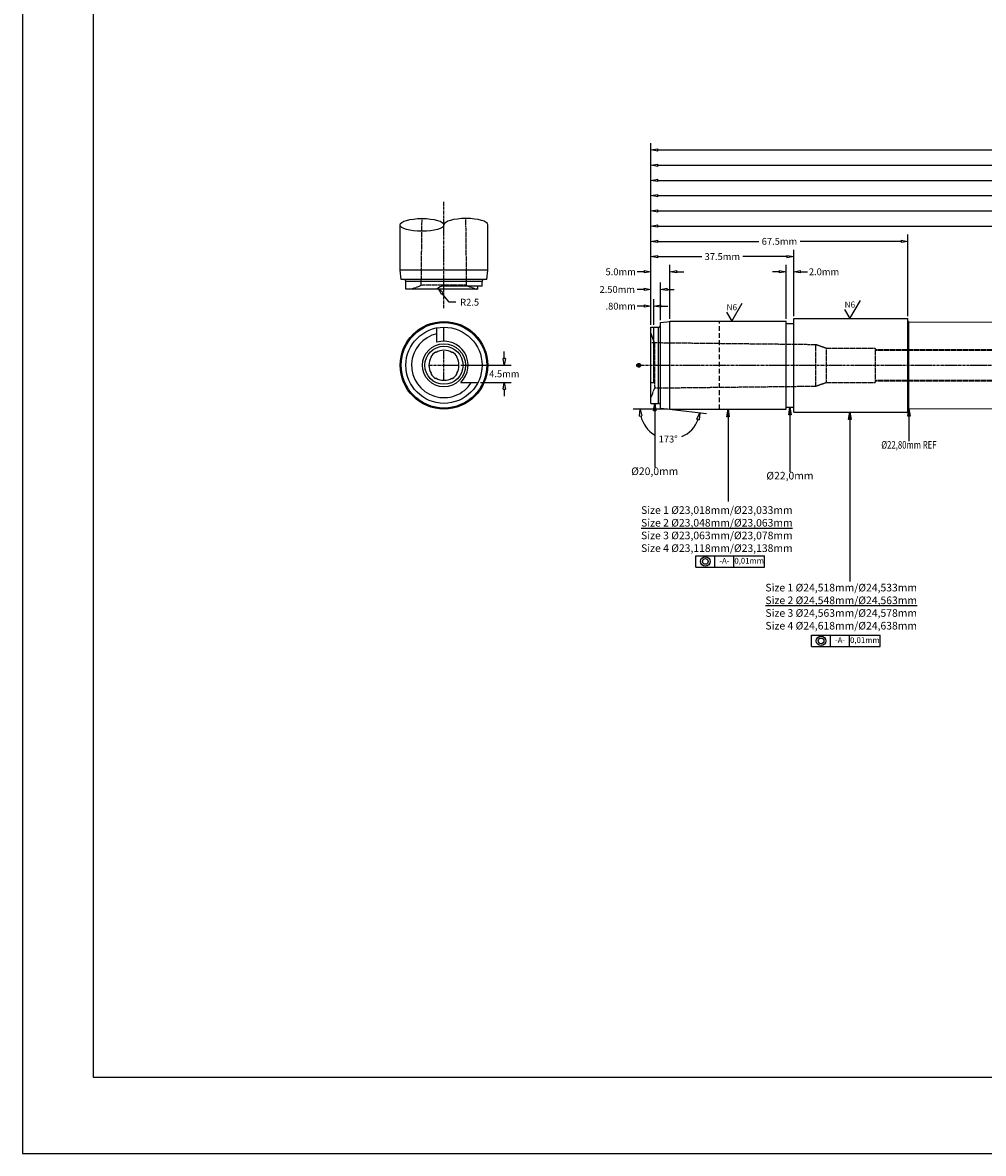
# Model space of a CAD drawing. Units: inches. Extents: x 0 to 841, y 0 to 594.
# Drawn here: x 0 to 252, y 0 to 297 of the extents above; entities that cross this region are included whole.
import ezdxf
from ezdxf.enums import TextEntityAlignment as Align

# ---------------------------------------------------------------- set-up
doc = ezdxf.new("R2010")
doc.units = ezdxf.units.IN
doc.header["$MEASUREMENT"] = 0
doc.linetypes.add('CENTER2', pattern=[1.125, 0.75, -0.125, 0.125, -0.125])
doc.linetypes.add('HIDDEN2', pattern=[0.1875, 0.125, -0.0625])
for name, color, linetype in [('CENTER', 1, 'CENTER2'), ('CENTERLINE', 1, 'CENTER2'), ('HIDDEN', 5, 'HIDDEN2'), ('TEXT', 5, 'Continuous')]:
    doc.layers.add(name, color=color, linetype=linetype)
doc.dimstyles.get("Standard").update_dxf_attribs({"dimscale": 10, "dimtxt": 0.18, "dimasz": 0.18, "dimexe": 0.18, "dimexo": 0.0625, "dimgap": 0.09, "dimtad": 0, "dimtih": 1, "dimtoh": 1, "dimdec": 4, "dimzin": 0, "dimdsep": 46, "dimtxsty": 'Standard', "dimblk": 'CLOSEDBLANK', "dimcen": 0.09, "dimadec": 4, "dimazin": 0, "dimtfac": 1, "dimtdec": 4, "dimtofl": 0, "dimtmove": 0, "dimatfit": 3, "dimldrblk": 'CLOSEDBLANK', "dimfxl": 0, "dimtolj": 1, "dimtzin": 0, "dimarcsym": 0})
doc.dimstyles.new('Standard$0', dxfattribs={"dimscale": 10, "dimtxt": 0.18, "dimasz": 0.18, "dimexe": 0.18, "dimexo": 0.0625, "dimgap": 0.09, "dimtad": 0, "dimtih": 1, "dimtoh": 1, "dimdec": 4, "dimzin": 4, "dimdsep": 46, "dimtxsty": 'Standard', "dimblk": 'CLOSEDBLANK', "dimcen": 0.09, "dimadec": 5, "dimazin": 1, "dimtfac": 1, "dimtdec": 4, "dimtofl": 0, "dimtmove": 0, "dimatfit": 3, "dimldrblk": 'CLOSEDBLANK', "dimfxl": 0, "dimtolj": 1, "dimtzin": 0, "dimarcsym": 0})

# ---------------------------------------------------------------- blocks, each defined once
blk = doc.blocks.new('_ClosedBlank')
at = {"color": 0, "linetype": 'ByBlock', "lineweight": -2}
for p, q in [((-1, 0.17), (0, 0)), ((-1, 0.17), (-1, -0.17)), ((0, 0), (-1, -0.17))]:
    blk.add_line(p, q, dxfattribs=at)
blk = doc.blocks.new('*D7')
at = {"color": 0, "lineweight": -2}
for p, q in [((165, 217.63), (165, 233.35)), ((170, 219.19), (170, 233.35)), ((163.2, 231.55), (161.4, 231.55)), ((171.8, 231.55), (173.6, 231.55))]:
    blk.add_line(p, q, dxfattribs=at)
at = {"layer": 'Defpoints', "color": 0}
for p in [(170, 231.55), (165, 217), (170, 218.57)]:
    blk.add_point(p, dxfattribs=at)
at = {"color": 0, "lineweight": -2, "xscale": 1.8, "yscale": 1.8, "zscale": 1.8}
blk.add_blockref('_ClosedBlank', (165, 231.55), dxfattribs=at)
at = {"color": 0, "lineweight": -2, "xscale": 1.8, "yscale": 1.8, "zscale": 1.8, "rotation": 180}
blk.add_blockref('_ClosedBlank', (170, 231.55), dxfattribs=at)
at = {"color": 0, "insert": (157.05, 231.55), "char_height": 1.8, "attachment_point": 5}
blk.add_mtext('\\A1;5.0mm', dxfattribs=at)
blk = doc.blocks.new('*D8')
at = {"color": 0, "lineweight": -2}
for p, q in [((165, 217.63), (165, 237.35)), ((166.8, 235.55), (178.35, 235.55)), ((200.7, 235.55), (189.15, 235.55)), ((202.5, 219.9), (202.5, 237.35))]:
    blk.add_line(p, q, dxfattribs=at)
at = {"layer": 'Defpoints', "color": 0}
for p in [(202.5, 235.55), (165, 217), (202.5, 219.28)]:
    blk.add_point(p, dxfattribs=at)
at = {"color": 0, "lineweight": -2, "xscale": 1.8, "yscale": 1.8, "zscale": 1.8, "rotation": 180}
blk.add_blockref('_ClosedBlank', (165, 235.55), dxfattribs=at)
at = {"color": 0, "lineweight": -2, "xscale": 1.8, "yscale": 1.8, "zscale": 1.8}
blk.add_blockref('_ClosedBlank', (202.5, 235.55), dxfattribs=at)
at = {"color": 0, "insert": (183.75, 235.55), "char_height": 1.8, "attachment_point": 5}
blk.add_mtext('\\A1;37.5mm', dxfattribs=at)
blk = doc.blocks.new('*D9')
at = {"color": 0, "lineweight": -2}
for p, q in [((165, 217.63), (165, 241.35)), ((232.5, 219.9), (232.5, 241.35)), ((166.8, 239.55), (193.35, 239.55)), ((230.7, 239.55), (204.15, 239.55))]:
    blk.add_line(p, q, dxfattribs=at)
at = {"layer": 'Defpoints', "color": 0}
for p in [(165, 239.55), (165, 217), (232.5, 219.28)]:
    blk.add_point(p, dxfattribs=at)
at = {"color": 0, "lineweight": -2, "xscale": 1.8, "yscale": 1.8, "zscale": 1.8, "rotation": 180}
blk.add_blockref('_ClosedBlank', (165, 239.55), dxfattribs=at)
at = {"color": 0, "lineweight": -2, "xscale": 1.8, "yscale": 1.8, "zscale": 1.8}
blk.add_blockref('_ClosedBlank', (232.5, 239.55), dxfattribs=at)
at = {"color": 0, "insert": (198.75, 239.55), "char_height": 1.8, "attachment_point": 5}
blk.add_mtext('\\A1;67.5mm', dxfattribs=at)
blk = doc.blocks.new('*D10')
at = {"color": 0, "lineweight": -2}
for p, q in [((165, 217.63), (165, 245.35)), ((166.8, 243.55), (262.5, 243.55)), ((370.2, 243.55), (274.5, 243.55)), ((372, 218.63), (372, 245.35))]:
    blk.add_line(p, q, dxfattribs=at)
at = {"layer": 'Defpoints', "color": 0}
for p in [(165, 243.55), (165, 217), (372, 218)]:
    blk.add_point(p, dxfattribs=at)
at = {"color": 0, "lineweight": -2, "xscale": 1.8, "yscale": 1.8, "zscale": 1.8, "rotation": 180}
blk.add_blockref('_ClosedBlank', (165, 243.55), dxfattribs=at)
at = {"color": 0, "lineweight": -2, "xscale": 1.8, "yscale": 1.8, "zscale": 1.8}
blk.add_blockref('_ClosedBlank', (372, 243.55), dxfattribs=at)
at = {"color": 0, "insert": (268.5, 243.55), "char_height": 1.8, "attachment_point": 5}
blk.add_mtext('\\A1;207.0mm', dxfattribs=at)
blk = doc.blocks.new('*D11')
at = {"color": 0, "lineweight": -2}
for p, q in [((165, 217.63), (165, 249.35)), ((166.8, 247.55), (274, 247.55)), ((393.2, 247.55), (286, 247.55)), ((395, 218.33), (395, 249.35))]:
    blk.add_line(p, q, dxfattribs=at)
at = {"layer": 'Defpoints', "color": 0}
for p in [(165, 247.55), (165, 217), (395, 217.7)]:
    blk.add_point(p, dxfattribs=at)
at = {"color": 0, "lineweight": -2, "xscale": 1.8, "yscale": 1.8, "zscale": 1.8, "rotation": 180}
blk.add_blockref('_ClosedBlank', (165, 247.55), dxfattribs=at)
at = {"color": 0, "lineweight": -2, "xscale": 1.8, "yscale": 1.8, "zscale": 1.8}
blk.add_blockref('_ClosedBlank', (395, 247.55), dxfattribs=at)
at = {"color": 0, "insert": (280, 247.55), "char_height": 1.8, "attachment_point": 5}
blk.add_mtext('\\A1;230.0mm', dxfattribs=at)
blk = doc.blocks.new('*D12')
at = {"color": 0, "lineweight": -2}
for p, q in [((165, 217.63), (165, 253.35)), ((447, 217.38), (447, 253.35)), ((166.8, 251.55), (299.85, 251.55)), ((445.2, 251.55), (312.15, 251.55))]:
    blk.add_line(p, q, dxfattribs=at)
at = {"layer": 'Defpoints', "color": 0}
for p in [(165, 251.55), (165, 217), (447, 216.75)]:
    blk.add_point(p, dxfattribs=at)
at = {"color": 0, "lineweight": -2, "xscale": 1.8, "yscale": 1.8, "zscale": 1.8, "rotation": 180}
blk.add_blockref('_ClosedBlank', (165, 251.55), dxfattribs=at)
at = {"color": 0, "lineweight": -2, "xscale": 1.8, "yscale": 1.8, "zscale": 1.8}
blk.add_blockref('_ClosedBlank', (447, 251.55), dxfattribs=at)
at = {"color": 0, "insert": (306, 251.55), "char_height": 1.8, "attachment_point": 5}
blk.add_mtext('\\A1;282.0mm', dxfattribs=at)
blk = doc.blocks.new('*D13')
at = {"color": 0, "lineweight": -2}
for p, q in [((165, 217.63), (165, 257.35)), ((166.8, 255.55), (320.85, 255.55)), ((487.2, 255.55), (333.15, 255.55)), ((489, 217.13), (489, 257.35))]:
    blk.add_line(p, q, dxfattribs=at)
at = {"layer": 'Defpoints', "color": 0}
for p in [(165, 255.55), (165, 217), (489, 216.5)]:
    blk.add_point(p, dxfattribs=at)
at = {"color": 0, "lineweight": -2, "xscale": 1.8, "yscale": 1.8, "zscale": 1.8, "rotation": 180}
blk.add_blockref('_ClosedBlank', (165, 255.55), dxfattribs=at)
at = {"color": 0, "lineweight": -2, "xscale": 1.8, "yscale": 1.8, "zscale": 1.8}
blk.add_blockref('_ClosedBlank', (489, 255.55), dxfattribs=at)
at = {"color": 0, "insert": (327, 255.55), "char_height": 1.8, "attachment_point": 5}
blk.add_mtext('\\A1;324.0mm', dxfattribs=at)
blk = doc.blocks.new('*D14')
at = {"color": 0, "lineweight": -2}
for p, q in [((165, 217.63), (165, 261.35)), ((166.8, 259.55), (413.6, 259.55)), ((672.7, 259.55), (425.9, 259.55)), ((674.5, 215.38), (674.5, 261.35))]:
    blk.add_line(p, q, dxfattribs=at)
at = {"layer": 'Defpoints', "color": 0}
for p in [(674.5, 259.55), (165, 217), (674.5, 214.75)]:
    blk.add_point(p, dxfattribs=at)
at = {"color": 0, "lineweight": -2, "xscale": 1.8, "yscale": 1.8, "zscale": 1.8, "rotation": 180}
blk.add_blockref('_ClosedBlank', (165, 259.55), dxfattribs=at)
at = {"color": 0, "lineweight": -2, "xscale": 1.8, "yscale": 1.8, "zscale": 1.8}
blk.add_blockref('_ClosedBlank', (674.5, 259.55), dxfattribs=at)
at = {"color": 0, "insert": (419.75, 259.55), "char_height": 1.8, "attachment_point": 5}
blk.add_mtext('\\A1;509.5mm', dxfattribs=at)
blk = doc.blocks.new('*D15')
at = {"color": 0, "lineweight": -2}
for p, q in [((165, 217.63), (165, 265.35)), ((715, 214.65), (715, 265.35)), ((166.8, 263.55), (434, 263.55)), ((713.2, 263.55), (446, 263.55))]:
    blk.add_line(p, q, dxfattribs=at)
at = {"layer": 'Defpoints', "color": 0}
for p in [(715, 263.55), (165, 217), (715, 214.03)]:
    blk.add_point(p, dxfattribs=at)
at = {"color": 0, "lineweight": -2, "xscale": 1.8, "yscale": 1.8, "zscale": 1.8, "rotation": 180}
blk.add_blockref('_ClosedBlank', (165, 263.55), dxfattribs=at)
at = {"color": 0, "lineweight": -2, "xscale": 1.8, "yscale": 1.8, "zscale": 1.8}
blk.add_blockref('_ClosedBlank', (715, 263.55), dxfattribs=at)
at = {"color": 0, "insert": (440, 263.55), "char_height": 1.8, "attachment_point": 5}
blk.add_mtext('\\A1;550.0mm', dxfattribs=at)
blk = doc.blocks.new('*D16')
at = {"color": 0, "lineweight": -2}
for p, q in [((200.5, 219.19), (200.5, 233.35)), ((202.5, 219.9), (202.5, 233.35)), ((198.7, 231.55), (196.9, 231.55)), ((204.3, 231.55), (206.1, 231.55))]:
    blk.add_line(p, q, dxfattribs=at)
at = {"layer": 'Defpoints', "color": 0}
for p in [(202.5, 231.55), (200.5, 218.57), (202.5, 219.28)]:
    blk.add_point(p, dxfattribs=at)
at = {"color": 0, "lineweight": -2, "xscale": 1.8, "yscale": 1.8, "zscale": 1.8}
blk.add_blockref('_ClosedBlank', (200.5, 231.55), dxfattribs=at)
at = {"color": 0, "lineweight": -2, "xscale": 1.8, "yscale": 1.8, "zscale": 1.8, "rotation": 180}
blk.add_blockref('_ClosedBlank', (202.5, 231.55), dxfattribs=at)
at = {"color": 0, "insert": (210.45, 231.55), "char_height": 1.8, "attachment_point": 5}
blk.add_mtext('\\A1;2.0mm', dxfattribs=at)
blk = doc.blocks.new('*D18')
at = {"color": 0, "lineweight": -2}
for p, q in [((169.38, 195.47), (160.34, 195.47)), ((170.62, 195.39), (179.59, 194.29))]:
    blk.add_line(p, q, dxfattribs=at)
for start, end in [(193.089, 238.7085), (293.3479, 339.8547)]:
    blk.add_arc((170, 195.47), 7.86, start, end, dxfattribs=at)
at = {"layer": 'Defpoints', "color": 0}
for p in [(167.5, 195.77), (170, 195.47), (170, 195.47), (200.5, 195.44), (165.79, 188.82)]:
    blk.add_point(p, dxfattribs=at)
at = {"color": 0, "lineweight": -2, "xscale": 1.8, "yscale": 1.8, "zscale": 1.8}
for p, rotation in [((162.14, 195.47), 96.51630221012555), ((177.8, 194.51), 76.42734130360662)]:
    blk.add_blockref('_ClosedBlank', p, dxfattribs=dict(at, rotation=rotation))
at = {"color": 0, "insert": (169.52, 187.62), "char_height": 1.8, "attachment_point": 5}
blk.add_mtext('\\A1;173°', dxfattribs=at)
blk = doc.blocks.new('*D19')
at = {"color": 0, "lineweight": -2}
for p, q in [((126.5, 208.8), (126.5, 210.6)), ((115.09, 207), (128.3, 207)), ((120.21, 202.5), (128.3, 202.5)), ((126.5, 200.7), (126.5, 198.9))]:
    blk.add_line(p, q, dxfattribs=at)
at = {"layer": 'Defpoints', "color": 0}
for p in [(114.46, 207), (126.5, 207), (119.58, 202.5)]:
    blk.add_point(p, dxfattribs=at)
at = {"color": 0, "lineweight": -2, "xscale": 1.8, "yscale": 1.8, "zscale": 1.8}
for p, rotation in [((126.5, 207), 270), ((126.5, 202.5), 90)]:
    blk.add_blockref('_ClosedBlank', p, dxfattribs=dict(at, rotation=rotation))
at = {"color": 0, "insert": (126.5, 204.75), "char_height": 1.8, "attachment_point": 5}
blk.add_mtext('\\A1;4.5mm', dxfattribs=at)
blk = doc.blocks.new('*D20')
at = {"color": 0, "lineweight": -2}
for p, q in [((111.99, 223.56), (110.22, 225.85)), ((113.79, 223.56), (111.99, 223.56))]:
    blk.add_line(p, q, dxfattribs=at)
at = {"layer": 'Defpoints', "color": 0}
for p in [(109.12, 227.28), (110.65, 225.3)]:
    blk.add_point(p, dxfattribs=at)
at = {"color": 0, "lineweight": -2, "xscale": 1.8, "yscale": 1.8, "zscale": 1.8, "rotation": 127.7379653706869}
blk.add_blockref('_ClosedBlank', (109.12, 227.28), dxfattribs=at)
at = {"color": 0, "insert": (117.39, 223.56), "char_height": 1.8, "attachment_point": 5}
blk.add_mtext('\\A1;R2.5', dxfattribs=at)
blk = doc.blocks.new('*D21')
at = {"color": 0, "lineweight": -2}
for p, q in [((165, 217.63), (165, 224.33)), ((165.8, 217.63), (165.8, 224.33)), ((163.2, 222.53), (161.4, 222.53)), ((167.6, 222.53), (169.4, 222.53))]:
    blk.add_line(p, q, dxfattribs=at)
at = {"layer": 'Defpoints', "color": 0}
for p in [(165.8, 222.53), (165, 217), (165.8, 217)]:
    blk.add_point(p, dxfattribs=at)
at = {"color": 0, "lineweight": -2, "xscale": 1.8, "yscale": 1.8, "zscale": 1.8}
blk.add_blockref('_ClosedBlank', (165, 222.53), dxfattribs=at)
at = {"color": 0, "lineweight": -2, "xscale": 1.8, "yscale": 1.8, "zscale": 1.8, "rotation": 180}
blk.add_blockref('_ClosedBlank', (165.8, 222.53), dxfattribs=at)
at = {"color": 0, "insert": (157.05, 222.53), "char_height": 1.8, "attachment_point": 5}
blk.add_mtext('\\A1;.80mm', dxfattribs=at)
blk = doc.blocks.new('*D22')
at = {"color": 0, "lineweight": -2}
for p, q in [((165, 217.63), (165, 228.71)), ((167.5, 218.85), (167.5, 228.71)), ((163.2, 226.91), (161.4, 226.91)), ((169.3, 226.91), (171.1, 226.91))]:
    blk.add_line(p, q, dxfattribs=at)
at = {"layer": 'Defpoints', "color": 0}
for p in [(167.5, 226.91), (165, 217), (167.5, 218.23)]:
    blk.add_point(p, dxfattribs=at)
at = {"color": 0, "lineweight": -2, "xscale": 1.8, "yscale": 1.8, "zscale": 1.8}
blk.add_blockref('_ClosedBlank', (165, 226.91), dxfattribs=at)
at = {"color": 0, "lineweight": -2, "xscale": 1.8, "yscale": 1.8, "zscale": 1.8, "rotation": 180}
blk.add_blockref('_ClosedBlank', (167.5, 226.91), dxfattribs=at)
at = {"color": 0, "insert": (156.15, 226.91), "char_height": 1.8, "attachment_point": 5}
blk.add_mtext('\\A1;2.50mm', dxfattribs=at)

msp = doc.modelspace()

# ---------------------------------------------------------------- hatches: boundary and pattern name
at = {"layer": 'CENTER'}
h = msp.add_hatch(dxfattribs=at)
h.set_pattern_fill('ANSI31', color=256, style=0)
h.set_pattern_definition([(45, (112.80006, 157), (-0.08838835, 0.08838835), [])])
h.paths.add_polyline_path([(161.80002, 207.50003, 0.414213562), (161.30002, 207.00003), (161.80002, 207.00003)])
h.paths.add_polyline_path([(162.30002, 207.00003), (161.80002, 207.00003), (161.80002, 206.50003, 0.414213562)])

# ---------------------------------------------------------------- linework, layer by layer
for p, q in [((99.11502, 232.00003), (99.11502, 243.86689)), ((122.18502, 232.00003), (122.18502, 243.86689)), ((122.18502, 232.00003), (99.11502, 232.00003)), ((99.42198, 229.50003), (99.11502, 232.00003)), ((121.87806, 229.50003), (122.18502, 232.00003)), ((121.87806, 229.50003), (99.42198, 229.50003)), ((100.65002, 227.00003), (100.65002, 229.00003)), ((120.65002, 229.00003), (100.65002, 229.00003)), ((120.65002, 227.80003), (120.65002, 229.00003)), ((119.5803, 227.00003), (100.65002, 227.00003)), ((120.65002, 227.80003), (110.65002, 227.80003)), ((119.5803, 227.00003), (119.5803, 227.80003)), ((186.25002, 218.56503), (188.99965, 223.32753)), ((217.25002, 219.27503), (219.99965, 224.03753)), ((184.8752, 220.94628), (186.25002, 218.56503)), ((215.8752, 221.65628), (217.25002, 219.27503)), ((108.81699, 213.05965), (108.81699, 216.83059)), ((110.65002, 213.33083), (110.65002, 217.00003)), ((165.00002, 197.00003), (165.00002, 217.00003)), ((165.00002, 217.00003), (167.00002, 217.00003)), ((165.80002, 202.50003), (165.80002, 217.00003)), ((167.00002, 197.00003), (167.00002, 217.00003)), ((167.50002, 218.22807), (170.00002, 218.53503)), ((167.50002, 218.22807), (170.00002, 218.53503)), ((167.50002, 195.77199), (167.50002, 218.22807)), ((170.00002, 218.56503), (200.50002, 218.56503)), ((170.00002, 195.43503), (170.00002, 218.56503)), ((200.50002, 195.43503), (200.50002, 218.56503)), ((200.50002, 218.00003), (202.50002, 218.00003)), ((202.50002, 194.72503), (202.50002, 219.27503)), ((202.50002, 219.27503), (232.50002, 219.27503)), ((232.50002, 194.72503), (232.50002, 219.27503)), ((232.75002, 218.40003), (372.00002, 218.00003)), ((232.75002, 195.60003), (232.75002, 218.40003)), ((165.80002, 213.30205), (165.00002, 215.50003)), ((107.30459, 209.09076), (107.19222, 209.20313)), ((108.55929, 210.34546), (108.44692, 210.45783)), ((112.74074, 210.34546), (112.85311, 210.45783)), ((113.99544, 209.09076), (114.10781, 209.20313)), ((107.30459, 204.9093), (107.19222, 204.79693)), ((108.55929, 203.6546), (108.44692, 203.54223)), ((112.74074, 203.6546), (112.85311, 203.54223)), ((113.99544, 204.9093), (114.10781, 204.79693)), ((115.103, 202.50003), (119.5803, 202.50003)), ((165.00002, 202.50003), (165.80002, 202.50003)), ((165.00002, 197.00003), (167.00002, 197.00003)), ((167.50002, 195.77199), (170.00002, 195.46503)), ((167.50002, 195.77199), (170.00002, 195.46503)), ((170.00002, 195.43503), (200.50002, 195.43503)), ((200.50002, 196.00003), (202.50002, 196.00003)), ((202.50002, 194.72503), (232.50002, 194.72503)), ((232.75002, 195.60003), (372.00002, 196.00003)), ((176.78966, 153.97), (176.78966, 156.97))]:
    msp.add_line(p, q)
at = {"linetype": 'HIDDEN2', "ltscale": 10}
msp.add_line((183.00002, 195.43503), (183.00002, 218.56503), dxfattribs=at)
for points in [[(-0.00009, 0.00003), (840.99991, 0.00003), (840.99991, 594.00003), (-0.00009, 594.00003)], [(18.49991, 20.00003), (822.49991, 20.00003), (822.49991, 574.00003), (18.49991, 574.00003)]]:
    msp.add_lwpolyline(points, close=True)
for radius in [11.5, 11.22804, 10, 5.67115, 5]:
    msp.add_circle((110.65002, 207.00003), radius)
for centre, radius, start, end in [((100.15002, 229.00003), 0.5, 0, 90), ((121.15002, 229.00003), 0.5, 90, 180), ((110.65002, 225.30003), 2.5, 90, 137.156357), ((167.00002, 217.50003), 0.5, 270, 0), ((232.75002, 218.65003), 0.25, 180, 270), ((110.65002, 207.00003), 8.5, 102.4537006, 328.0342812), ((110.65002, 207.00003), 3.945, 57.9966569, 122.0033431), ((110.65002, 207.00003), 6.3308, 314.6990904, 106.8305173), ((110.65002, 207.00003), 3.945, 147.9966569, 212.0033431), ((110.65002, 207.00003), 4.1, 122.5027882, 147.4972118), ((110.65002, 207.00003), 4.1, 32.5027882, 57.4972118), ((110.65002, 207.00003), 3.945, 327.9966569, 32.0033431), ((110.65002, 207.00003), 4.1, 212.5027882, 237.4972118), ((110.65002, 207.00003), 3.945, 237.9966569, 302.0033431), ((110.65002, 207.00003), 4.1, 302.5027882, 327.4972118), ((167.00002, 196.50003), 0.5, 0, 90), ((232.75002, 195.35003), 0.25, 90, 180)]:
    msp.add_arc(centre, radius, start, end)
msp.add_ellipse((104.88252, 243.86689), major_axis=(-5.7675, 0), ratio=0.291449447)
msp.add_ellipse((116.41752, 243.86689), major_axis=(-5.7675, 0), ratio=0.291449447, start_param=3.141592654, end_param=6.283185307)
at = {"layer": 'CENTER'}
msp.add_line((161.80002, 206.50003), (161.80002, 207.50003), dxfattribs=at)
msp.add_circle((161.80002, 207.00003), 0.5, dxfattribs=at)
at = {"layer": 'CENTERLINE'}
for p, q in [((110.65002, 222.00003), (110.65002, 249.89728)), ((110.65002, 203.19003), (110.65002, 210.81003)), ((106.84002, 207.00003), (114.46002, 207.00003)), ((161.30002, 207.00003), (718.00002, 207.00003))]:
    msp.add_line(p, q, dxfattribs=at)
at = {"layer": 'HIDDEN'}
for p, q in [((104.68835, 227.92391), (104.89124, 245.54782)), ((116.61168, 227.92391), (116.40879, 245.54782)), ((104.97885, 228.02964), (102.15002, 227.00003)), ((116.32119, 228.02964), (104.97885, 228.02964)), ((116.32119, 228.02964), (119.15002, 227.00003)), ((165.20004, 212.97003), (208.2926, 212.47393)), ((166.02963, 212.6712), (165.80002, 213.30205)), ((166.02963, 201.32886), (166.02963, 212.6712)), ((208.2926, 212.47393), (211.11945, 211.49503)), ((208.2926, 201.52613), (208.2926, 212.47393)), ((208.3692, 212.44741), (211.11945, 211.49503)), ((211.11945, 211.49503), (224.01002, 211.49503)), ((211.11945, 202.50503), (211.11945, 211.49503)), ((224.01002, 202.50503), (224.01002, 211.49503)), ((224.01002, 211.10003), (715.00002, 211.10003)), ((224.01002, 210.94503), (715.00002, 210.94503)), ((208.2926, 201.52613), (211.03996, 202.4775)), ((208.3692, 201.55265), (211.11945, 202.50503)), ((211.11945, 202.50503), (224.01002, 202.50503)), ((224.01002, 203.05503), (715.00002, 203.05503)), ((224.01002, 202.90003), (715.00002, 202.90003)), ((166.02963, 201.32886), (165.00002, 198.50003)), ((166.02963, 201.32886), (165.80002, 200.69801)), ((165.92389, 201.03836), (208.2926, 201.52613))]:
    msp.add_line(p, q, dxfattribs=at)
at = {"layer": 'TEXT', "color": 7}
for p, q in [((176.78966, 156.97), (181.78966, 156.97)), ((181.78966, 156.97), (186.78966, 156.97)), ((181.78966, 153.97), (181.78966, 156.97)), ((186.78966, 156.97), (194.78966, 156.97)), ((186.78966, 153.97), (186.78966, 156.97)), ((194.78966, 153.97), (194.78966, 156.97)), ((176.78966, 153.97), (181.78966, 153.97)), ((181.78966, 153.97), (186.78966, 153.97)), ((186.78966, 153.97), (194.78966, 153.97)), ((207.1743, 133.1172), (207.1743, 136.1172)), ((207.1743, 136.1172), (212.1743, 136.1172)), ((212.1743, 136.1172), (217.1743, 136.1172)), ((212.1743, 133.1172), (212.1743, 136.1172)), ((217.1743, 136.1172), (225.1743, 136.1172)), ((217.1743, 133.1172), (217.1743, 136.1172)), ((225.1743, 133.1172), (225.1743, 136.1172)), ((207.1743, 133.1172), (212.1743, 133.1172)), ((212.1743, 133.1172), (217.1743, 133.1172)), ((217.1743, 133.1172), (225.1743, 133.1172))]:
    msp.add_line(p, q, dxfattribs=at)
for centre, radius in [((179.28966, 155.47), 1.25), ((179.28966, 155.47), 0.75), ((209.6743, 134.6172), 1.25), ((209.6743, 134.6172), 0.75)]:
    msp.add_circle(centre, radius, dxfattribs=at)

# ---------------------------------------------------------------- texts
for p in [(186.25002, 220.94628), (217.25002, 221.65628)]:
    msp.add_text('N6', height=1.5875).set_placement(p, align=Align.BOTTOM_CENTER)
at = {"char_height": 2, "attachment_point": 2}
for s, insert, width in [('\\A1;{\\W0.75;%%C22,80mm REF}', (232.75002, 187.10003), 28.6395508), ('\\A1;%%C20,0mm', (166.00002, 180.16881), 10.5482646), ('\\A1;%%C22,0mm', (201.50002, 179.00003), 10.5482646)]:
    msp.add_mtext(s, dxfattribs=dict(at, insert=insert, width=width))
at = {"layer": 'TEXT', "color": 7}
for s, insert, char_height, width, attachment_point in [('\\A1;Size 1 %%C23,018mm/%%C23,033mm\\P{\\LSize 2 %%C23,048mm/%%C23,063mm}\\PSize 3 %%C23,063mm/%%C23,078mm\\PSize 4 %%C23,118mm/%%C23,138mm', (162.4046, 169.97), 2, 48.5376086, 1), ('-A-', (184.28966, 155.47), 1.5, 1.19634, 5), ('0,01mm', (190.78966, 155.47), 1.5, 6.6720954, 5), ('\\A1;Size 1 %%C24,518mm/%%C24,533mm\\P{\\LSize 2 %%C24,548mm/%%C24,563mm}\\PSize 3 %%C24,563mm/%%C24,578mm\\PSize 4 %%C24,618mm/%%C24,638mm', (195.06644, 149.60018), 2, 48.5376086, 1), ('-A-', (214.6743, 134.6172), 1.5, 1.19634, 5), ('0,01mm', (221.1743, 134.6172), 1.5, 6.6720954, 5)]:
    msp.add_mtext(s, dxfattribs=dict(at, insert=insert, char_height=char_height, width=width, attachment_point=attachment_point))

# ---------------------------------------------------------------- dimensions: what is measured, and where the dimension line sits
for base, p1, p2, picture, middle in [((715.00002, 263.5467), (165.00002, 217.00003), (715.00002, 214.02503), '*D15', (440.00002, 263.5467)), ((674.50002, 259.5467), (165.00002, 217.00003), (674.50002, 214.75003), '*D14', (419.75002, 259.5467)), ((165.00002, 255.54816), (489.00002, 216.50003), (165.00002, 217.00003), '*D13', (327.00002, 255.54816)), ((165.00002, 251.54962), (447.00002, 216.75003), (165.00002, 217.00003), '*D12', (306.00002, 251.54962)), ((165.00002, 247.55108), (395.00002, 217.70003), (165.00002, 217.00003), '*D11', (280.00002, 247.55108)), ((165.00002, 243.55254), (372.00002, 218.00003), (165.00002, 217.00003), '*D10', (268.50002, 243.55254)), ((165.00002, 239.54962), (232.50002, 219.27503), (165.00002, 217.00003), '*D9', (198.75002, 239.54962)), ((202.50002, 235.54962), (165.00002, 217.00003), (202.50002, 219.27503), '*D8', (183.75002, 235.54962)), ((202.50002, 231.54962), (200.50002, 218.56503), (202.50002, 219.27503), '*D16', (210.45002, 231.54962))]:
    dim = msp.add_linear_dim(base=base, p1=p1, p2=p2, dimstyle='Standard$0', override={"dimscale": 10, "dimdec": 1, "dimpost": 'mm', "dimblk1": 'ClosedBlank', "dimblk2": 'ClosedBlank', "dimsah": 1})
    dim.commit()
    dim.dimension.update_dxf_attribs({"geometry": picture, "text_midpoint": middle})
for base, p2, override, picture, middle in [((170.00002, 231.54962), (170.00002, 218.56503), {"dimscale": 10, "dimdec": 1, "dimpost": 'mm', "dimblk1": 'ClosedBlank', "dimblk2": 'ClosedBlank', "dimsah": 1}, '*D7', (157.05002, 231.54962)), ((167.50002, 226.91371), (167.50002, 218.22807), {"dimscale": 10, "dimdec": 2, "dimpost": 'mm', "dimblk1": 'ClosedBlank', "dimblk2": 'ClosedBlank', "dimsah": 1}, '*D22', (156.15002, 226.91371)), ((165.80002, 222.52503), (165.80002, 217.00003), {"dimscale": 10, "dimdec": 2, "dimpost": 'mm', "dimblk1": 'ClosedBlank', "dimblk2": 'ClosedBlank', "dimsah": 1}, '*D21', (157.05002, 222.52503))]:
    dim = msp.add_linear_dim(base=base, p1=(165.00002, 217.00003), p2=p2, dimstyle='Standard$0', override=override)
    dim.commit()
    dim.dimension.update_dxf_attribs({"geometry": picture, "text_midpoint": middle, "dimtype": 160})
dim = msp.add_radius_dim(center=(110.65002, 225.30003), mpoint=(109.11989, 227.27707), dimstyle='Standard', override={"dimdec": 1, "dimtmove": 1})
dim.commit()
dim.dimension.update_dxf_attribs({"geometry": '*D20', "text_midpoint": (111.99381, 223.56374), "dimtype": 164})
dim = msp.add_linear_dim(base=(126.49727, 207.00003), p1=(119.5803, 202.50003), p2=(114.46002, 207.00003), angle=90, dimstyle='Standard$0', override={"dimdec": 1, "dimpost": 'mm'})
dim.commit()
dim.dimension.update_dxf_attribs({"geometry": '*D19', "text_midpoint": (126.49727, 204.75003)})
dim = msp.add_angular_dim_2l(base=(165.79029, 188.82411), line1=((170.00002, 195.46503), (200.50002, 195.43503)), line2=((167.50002, 195.77199), (170.00002, 195.46503)), dimstyle='Standard', override={"dimadec": 0})
dim.commit()
dim.dimension.update_dxf_attribs({"geometry": '*D18', "text_midpoint": (169.51615, 187.61714)})

# ---------------------------------------------------------------- leaders
for points in [[(166.00002, 197.00003), (166.00002, 180.16881)], [(166.00002, 197.00003), (166.00002, 180.16881)], [(201.50002, 196.00003), (201.50002, 179.00003)], [(232.75002, 195.60003), (232.75002, 187.10003)]]:
    msp.add_leader(points, dimstyle='Standard', override={"dimscale": 1, "dimasz": 2, "dimgap": 0.09, "dimtad": 0, "dimldrblk": 'ClosedBlank'})
for points in [[(185.25002, 195.43503), (185.25002, 171.20901)], [(217.25002, 194.72503), (217.25002, 150.20279)]]:
    msp.add_leader(points, dimstyle='Standard', override={"dimscale": 1, "dimasz": 2, "dimgap": 0.09, "dimtad": 0, "dimldrblk": 'ClosedBlank'}, dxfattribs=at)

doc.saveas('drawing.dxf')
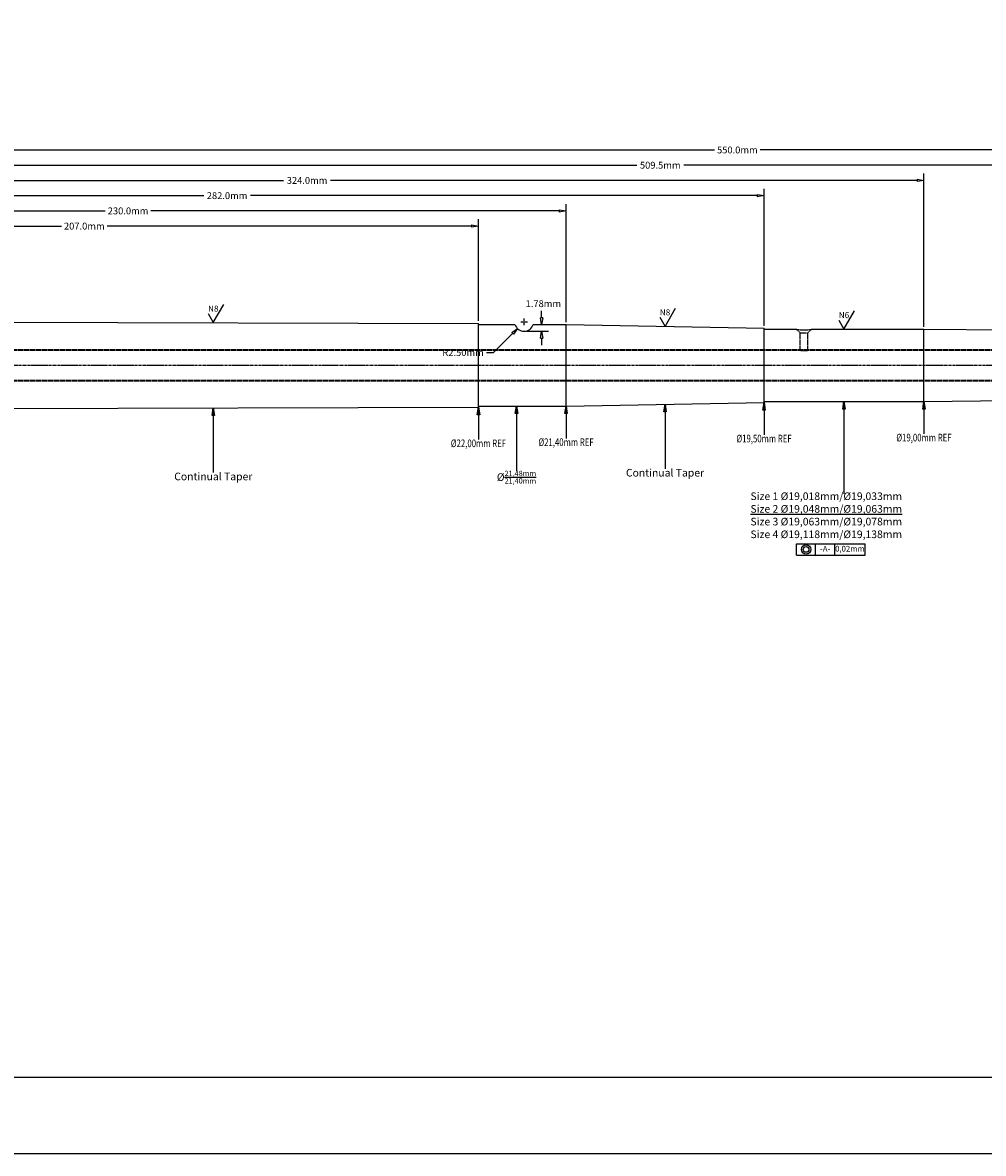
# Model space of a CAD drawing. Units: inches. Extents: x 0 to 841, y 0 to 594.
# Drawn here: x 252 to 505, y 0 to 297 of the extents above; entities that cross this region are included whole.
import ezdxf
from ezdxf.enums import TextEntityAlignment as Align

# ---------------------------------------------------------------- set-up
doc = ezdxf.new("R2010")
doc.units = ezdxf.units.IN
doc.header["$MEASUREMENT"] = 0
doc.linetypes.add('CENTER2', pattern=[1.125, 0.75, -0.125, 0.125, -0.125])
doc.linetypes.add('HIDDEN2', pattern=[0.1875, 0.125, -0.0625])
for name, color, linetype in [('CENTER', 1, 'CENTER2'), ('CENTERLINE', 1, 'CENTER2'), ('HIDDEN', 5, 'HIDDEN2'), ('TEXT', 5, 'Continuous')]:
    doc.layers.add(name, color=color, linetype=linetype)
doc.dimstyles.get("Standard").update_dxf_attribs({"dimscale": 10, "dimtxt": 0.18, "dimasz": 0.18, "dimexe": 0.18, "dimexo": 0.0625, "dimgap": 0.09, "dimtad": 0, "dimtih": 1, "dimtoh": 1, "dimdec": 4, "dimzin": 0, "dimdsep": 46, "dimtxsty": 'Standard', "dimblk": 'CLOSEDBLANK', "dimcen": 0.09, "dimadec": 4, "dimazin": 0, "dimtfac": 1, "dimtdec": 4, "dimtofl": 0, "dimtmove": 0, "dimatfit": 3, "dimldrblk": 'CLOSEDBLANK', "dimfxl": 0, "dimtolj": 1, "dimtzin": 0, "dimarcsym": 0})
doc.dimstyles.new('Standard$0', dxfattribs={"dimscale": 10, "dimtxt": 0.18, "dimasz": 0.18, "dimexe": 0.18, "dimexo": 0.0625, "dimgap": 0.09, "dimtad": 0, "dimtih": 1, "dimtoh": 1, "dimdec": 4, "dimzin": 4, "dimdsep": 46, "dimtxsty": 'Standard', "dimblk": 'CLOSEDBLANK', "dimcen": 0.09, "dimadec": 5, "dimazin": 1, "dimtfac": 1, "dimtdec": 4, "dimtofl": 0, "dimtmove": 0, "dimatfit": 3, "dimldrblk": 'CLOSEDBLANK', "dimfxl": 0, "dimtolj": 1, "dimtzin": 0, "dimarcsym": 0})

# ---------------------------------------------------------------- blocks, each defined once
blk = doc.blocks.new('_ClosedBlank')
at = {"color": 0, "linetype": 'ByBlock', "lineweight": -2}
for p, q in [((-1, 0.17), (0, 0)), ((-1, 0.17), (-1, -0.17)), ((0, 0), (-1, -0.17))]:
    blk.add_line(p, q, dxfattribs=at)
blk = doc.blocks.new('*D10')
at = {"color": 0, "lineweight": -2}
for p, q in [((165, 217.63), (165, 245.35)), ((166.8, 243.55), (262.5, 243.55)), ((370.2, 243.55), (274.5, 243.55)), ((372, 218.63), (372, 245.35))]:
    blk.add_line(p, q, dxfattribs=at)
at = {"layer": 'Defpoints', "color": 0}
for p in [(165, 243.55), (165, 217), (372, 218)]:
    blk.add_point(p, dxfattribs=at)
at = {"color": 0, "lineweight": -2, "xscale": 1.8, "yscale": 1.8, "zscale": 1.8, "rotation": 180}
blk.add_blockref('_ClosedBlank', (165, 243.55), dxfattribs=at)
at = {"color": 0, "lineweight": -2, "xscale": 1.8, "yscale": 1.8, "zscale": 1.8}
blk.add_blockref('_ClosedBlank', (372, 243.55), dxfattribs=at)
at = {"color": 0, "insert": (268.5, 243.55), "char_height": 1.8, "attachment_point": 5}
blk.add_mtext('\\A1;207.0mm', dxfattribs=at)
blk = doc.blocks.new('*D11')
at = {"color": 0, "lineweight": -2}
for p, q in [((165, 217.63), (165, 249.35)), ((166.8, 247.55), (274, 247.55)), ((393.2, 247.55), (286, 247.55)), ((395, 218.33), (395, 249.35))]:
    blk.add_line(p, q, dxfattribs=at)
at = {"layer": 'Defpoints', "color": 0}
for p in [(165, 247.55), (165, 217), (395, 217.7)]:
    blk.add_point(p, dxfattribs=at)
at = {"color": 0, "lineweight": -2, "xscale": 1.8, "yscale": 1.8, "zscale": 1.8, "rotation": 180}
blk.add_blockref('_ClosedBlank', (165, 247.55), dxfattribs=at)
at = {"color": 0, "lineweight": -2, "xscale": 1.8, "yscale": 1.8, "zscale": 1.8}
blk.add_blockref('_ClosedBlank', (395, 247.55), dxfattribs=at)
at = {"color": 0, "insert": (280, 247.55), "char_height": 1.8, "attachment_point": 5}
blk.add_mtext('\\A1;230.0mm', dxfattribs=at)
blk = doc.blocks.new('*D12')
at = {"color": 0, "lineweight": -2}
for p, q in [((165, 217.63), (165, 253.35)), ((447, 217.38), (447, 253.35)), ((166.8, 251.55), (299.85, 251.55)), ((445.2, 251.55), (312.15, 251.55))]:
    blk.add_line(p, q, dxfattribs=at)
at = {"layer": 'Defpoints', "color": 0}
for p in [(165, 251.55), (165, 217), (447, 216.75)]:
    blk.add_point(p, dxfattribs=at)
at = {"color": 0, "lineweight": -2, "xscale": 1.8, "yscale": 1.8, "zscale": 1.8, "rotation": 180}
blk.add_blockref('_ClosedBlank', (165, 251.55), dxfattribs=at)
at = {"color": 0, "lineweight": -2, "xscale": 1.8, "yscale": 1.8, "zscale": 1.8}
blk.add_blockref('_ClosedBlank', (447, 251.55), dxfattribs=at)
at = {"color": 0, "insert": (306, 251.55), "char_height": 1.8, "attachment_point": 5}
blk.add_mtext('\\A1;282.0mm', dxfattribs=at)
blk = doc.blocks.new('*D13')
at = {"color": 0, "lineweight": -2}
for p, q in [((165, 217.63), (165, 257.35)), ((166.8, 255.55), (320.85, 255.55)), ((487.2, 255.55), (333.15, 255.55)), ((489, 217.13), (489, 257.35))]:
    blk.add_line(p, q, dxfattribs=at)
at = {"layer": 'Defpoints', "color": 0}
for p in [(165, 255.55), (165, 217), (489, 216.5)]:
    blk.add_point(p, dxfattribs=at)
at = {"color": 0, "lineweight": -2, "xscale": 1.8, "yscale": 1.8, "zscale": 1.8, "rotation": 180}
blk.add_blockref('_ClosedBlank', (165, 255.55), dxfattribs=at)
at = {"color": 0, "lineweight": -2, "xscale": 1.8, "yscale": 1.8, "zscale": 1.8}
blk.add_blockref('_ClosedBlank', (489, 255.55), dxfattribs=at)
at = {"color": 0, "insert": (327, 255.55), "char_height": 1.8, "attachment_point": 5}
blk.add_mtext('\\A1;324.0mm', dxfattribs=at)
blk = doc.blocks.new('*D14')
at = {"color": 0, "lineweight": -2}
for p, q in [((165, 217.63), (165, 261.35)), ((166.8, 259.55), (413.6, 259.55)), ((672.7, 259.55), (425.9, 259.55)), ((674.5, 215.38), (674.5, 261.35))]:
    blk.add_line(p, q, dxfattribs=at)
at = {"layer": 'Defpoints', "color": 0}
for p in [(674.5, 259.55), (165, 217), (674.5, 214.75)]:
    blk.add_point(p, dxfattribs=at)
at = {"color": 0, "lineweight": -2, "xscale": 1.8, "yscale": 1.8, "zscale": 1.8, "rotation": 180}
blk.add_blockref('_ClosedBlank', (165, 259.55), dxfattribs=at)
at = {"color": 0, "lineweight": -2, "xscale": 1.8, "yscale": 1.8, "zscale": 1.8}
blk.add_blockref('_ClosedBlank', (674.5, 259.55), dxfattribs=at)
at = {"color": 0, "insert": (419.75, 259.55), "char_height": 1.8, "attachment_point": 5}
blk.add_mtext('\\A1;509.5mm', dxfattribs=at)
blk = doc.blocks.new('*D15')
at = {"color": 0, "lineweight": -2}
for p, q in [((165, 217.63), (165, 265.35)), ((715, 214.65), (715, 265.35)), ((166.8, 263.55), (434, 263.55)), ((713.2, 263.55), (446, 263.55))]:
    blk.add_line(p, q, dxfattribs=at)
at = {"layer": 'Defpoints', "color": 0}
for p in [(715, 263.55), (165, 217), (715, 214.03)]:
    blk.add_point(p, dxfattribs=at)
at = {"color": 0, "lineweight": -2, "xscale": 1.8, "yscale": 1.8, "zscale": 1.8, "rotation": 180}
blk.add_blockref('_ClosedBlank', (165, 263.55), dxfattribs=at)
at = {"color": 0, "lineweight": -2, "xscale": 1.8, "yscale": 1.8, "zscale": 1.8}
blk.add_blockref('_ClosedBlank', (715, 263.55), dxfattribs=at)
at = {"color": 0, "insert": (440, 263.55), "char_height": 1.8, "attachment_point": 5}
blk.add_mtext('\\A1;550.0mm', dxfattribs=at)
blk = doc.blocks.new('*D25')
at = {"color": 0, "lineweight": -2}
for p, q in [((388.6, 219.5), (388.6, 221.3)), ((387.04, 217.7), (390.4, 217.7)), ((384.63, 215.92), (390.4, 215.92)), ((388.6, 214.12), (388.6, 212.32))]:
    blk.add_line(p, q, dxfattribs=at)
at = {"layer": 'Defpoints', "color": 0}
for p in [(386.41, 217.7), (388.6, 217.7), (384, 215.92)]:
    blk.add_point(p, dxfattribs=at)
at = {"color": 0, "lineweight": -2, "xscale": 1.8, "yscale": 1.8, "zscale": 1.8}
for p, rotation in [((388.6, 217.7), 270), ((388.6, 215.92), 90)]:
    blk.add_blockref('_ClosedBlank', p, dxfattribs=dict(at, rotation=rotation))
at = {"color": 0, "insert": (389.05, 223.18), "char_height": 1.8, "attachment_point": 5}
blk.add_mtext('\\A1;1.78mm', dxfattribs=at)
blk = doc.blocks.new('*D26')
at = {"color": 0, "lineweight": -2}
for p, q in [((375.92, 210.34), (380.96, 215.38)), ((374.12, 210.34), (375.92, 210.34))]:
    blk.add_line(p, q, dxfattribs=at)
at = {"layer": 'Defpoints', "color": 0}
for p in [(384, 218.42), (382.23, 216.65)]:
    blk.add_point(p, dxfattribs=at)
at = {"color": 0, "lineweight": -2, "xscale": 1.8, "yscale": 1.8, "zscale": 1.8, "rotation": 44.99999999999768}
blk.add_blockref('_ClosedBlank', (382.23, 216.65), dxfattribs=at)
at = {"color": 0, "insert": (367.97, 210.34), "char_height": 1.8, "attachment_point": 5}
blk.add_mtext('\\A1;R2.50mm', dxfattribs=at)

msp = doc.modelspace()

# ---------------------------------------------------------------- linework, layer by layer
for p, q in [((302.37502, 218.20003), (305.12465, 222.96253)), ((301.0002, 220.58128), (302.37502, 218.20003)), ((421.00002, 217.22503), (423.74965, 221.98753)), ((468.00002, 216.50003), (470.74965, 221.26253)), ((232.75002, 218.40003), (372.00002, 218.00003)), ((372.00002, 196.00003), (372.00002, 218.00003)), ((372.00002, 217.70003), (381.60594, 217.70003)), ((386.39409, 217.70003), (395.00002, 217.70003)), ((395.00002, 217.70003), (447.00002, 216.75003)), ((395.00002, 196.30003), (395.00002, 217.70003)), ((419.6252, 219.60628), (421.00002, 217.22503)), ((466.6252, 218.88128), (468.00002, 216.50003)), ((447.00002, 197.25003), (447.00002, 216.75003)), ((447.00002, 216.50003), (455.50002, 216.50003)), ((459.50002, 216.50003), (489.00002, 216.50003)), ((489.00002, 216.50003), (674.50002, 214.75003)), ((489.00002, 197.50003), (489.00002, 216.50003)), ((489.00002, 197.50003), (674.50002, 199.25003)), ((372.00002, 196.30003), (395.00002, 196.30003)), ((395.00002, 196.30003), (447.00002, 197.25003)), ((447.00002, 197.50003), (489.00002, 197.50003)), ((232.75002, 195.60003), (372.00002, 196.00003))]:
    msp.add_line(p, q)
for points in [[(-0.00009, 0.00003), (840.99991, 0.00003), (840.99991, 594.00003), (-0.00009, 594.00003)], [(18.49991, 20.00003), (822.49991, 20.00003), (822.49991, 574.00003), (18.49991, 574.00003)]]:
    msp.add_lwpolyline(points, close=True)
msp.add_arc((384.00002, 218.42003), 2.5, 196.7382568, 343.2617432)
msp.add_ellipse((457.50002, 216.50003), major_axis=(-2, 0), ratio=0.088312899, start_param=0, end_param=3.141592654)
at = {"layer": 'CENTER'}
for p, q in [((383.10002, 218.42003), (384.90002, 218.42003)), ((384.00002, 217.52003), (384.00002, 219.32003))]:
    msp.add_line(p, q, dxfattribs=at)
at = {"layer": 'CENTERLINE'}
msp.add_line((161.30002, 207.00003), (718.00002, 207.00003), dxfattribs=at)
at = {"layer": 'HIDDEN'}
for p, q in [((455.50002, 216.50003), (456.50002, 215.50003)), ((456.50002, 210.97621), (456.50002, 215.50003)), ((456.50002, 215.50003), (458.50002, 215.50003)), ((459.50002, 216.50003), (458.50002, 215.50003)), ((458.50002, 210.97621), (458.50002, 215.50003)), ((224.01002, 211.10003), (715.00002, 211.10003)), ((224.01002, 210.94503), (715.00002, 210.94503)), ((224.01002, 203.05503), (715.00002, 203.05503)), ((224.01002, 202.90003), (715.00002, 202.90003))]:
    msp.add_line(p, q, dxfattribs=at)
msp.add_ellipse((457.50002, 210.97621), major_axis=(-1, 0), ratio=0.12382093, start_param=0, end_param=3.141592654, dxfattribs=at)
at = {"layer": 'TEXT', "color": 7}
for p, q in [((455.55386, 157.12308), (455.55386, 160.12308)), ((455.55386, 160.12308), (460.55386, 160.12308)), ((460.55386, 160.12308), (465.55386, 160.12308)), ((460.55386, 157.12308), (460.55386, 160.12308)), ((465.55386, 160.12308), (473.55386, 160.12308)), ((465.55386, 157.12308), (465.55386, 160.12308)), ((473.55386, 157.12308), (473.55386, 160.12308)), ((455.55386, 157.12308), (460.55386, 157.12308)), ((460.55386, 157.12308), (465.55386, 157.12308)), ((465.55386, 157.12308), (473.55386, 157.12308))]:
    msp.add_line(p, q, dxfattribs=at)
for radius in [1.25, 0.75]:
    msp.add_circle((458.05386, 158.62308), radius, dxfattribs=at)

# ---------------------------------------------------------------- texts
for s, p in [('N8', (302.37502, 220.58128)), ('N8', (421.00002, 219.60628)), ('N6', (468.00002, 218.88128))]:
    msp.add_text(s, height=1.5875).set_placement(p, align=Align.BOTTOM_CENTER)
at = {"char_height": 2, "attachment_point": 2}
for s, insert, width in [('\\A1;{\\W0.75;%%C22,00mm REF}', (372.00002, 187.50003), 28.6395508), ('\\A1;{\\W0.75;%%C21,40mm REF}', (395.00002, 187.80003), 28.6395508), ('\\A1;{\\W0.75;%%C19,50mm REF}', (447.00002, 188.75003), 28.6395508), ('\\A1;{\\W0.75;%%C19,00mm REF}', (489.00002, 189.00003), 28.6395508), ('\\A1;Continual Taper', (302.37502, 178.80003), 28.6395508), ('\\A1;%%C{\\H0.7x;\\S21,48mm/21,40mm;}', (382.00002, 179.30003), 11.6679531), ('\\A1;Continual Taper', (421.00002, 179.77503), 28.6395508)]:
    msp.add_mtext(s, dxfattribs=dict(at, insert=insert, width=width))
at = {"layer": 'TEXT', "color": 7}
for s, insert, char_height, width, attachment_point in [('\\A1;Size 1 %%C19,018mm/%%C19,033mm\\P{\\LSize 2 %%C19,048mm/%%C19,063mm}\\PSize 3 %%C19,063mm/%%C19,078mm\\PSize 4 %%C19,118mm/%%C19,138mm', (443.446, 173.60606), 2, 48.5376086, 1), ('-A-', (463.05386, 158.62308), 1.5, 1.19634, 5), ('0,02mm', (469.55386, 158.62308), 1.5, 6.6720954, 5)]:
    msp.add_mtext(s, dxfattribs=dict(at, insert=insert, char_height=char_height, width=width, attachment_point=attachment_point))

# ---------------------------------------------------------------- dimensions: what is measured, and where the dimension line sits
for base, p1, p2, picture, middle in [((715.00002, 263.5467), (165.00002, 217.00003), (715.00002, 214.02503), '*D15', (440.00002, 263.5467)), ((674.50002, 259.5467), (165.00002, 217.00003), (674.50002, 214.75003), '*D14', (419.75002, 259.5467)), ((165.00002, 255.54816), (489.00002, 216.50003), (165.00002, 217.00003), '*D13', (327.00002, 255.54816)), ((165.00002, 251.54962), (447.00002, 216.75003), (165.00002, 217.00003), '*D12', (306.00002, 251.54962)), ((165.00002, 247.55108), (395.00002, 217.70003), (165.00002, 217.00003), '*D11', (280.00002, 247.55108)), ((165.00002, 243.55254), (372.00002, 218.00003), (165.00002, 217.00003), '*D10', (268.50002, 243.55254))]:
    dim = msp.add_linear_dim(base=base, p1=p1, p2=p2, dimstyle='Standard$0', override={"dimscale": 10, "dimdec": 1, "dimpost": 'mm', "dimblk1": 'ClosedBlank', "dimblk2": 'ClosedBlank', "dimsah": 1})
    dim.commit()
    dim.dimension.update_dxf_attribs({"geometry": picture, "text_midpoint": middle})
dim = msp.add_linear_dim(base=(388.60002, 217.69803), p1=(384.00002, 215.92003), p2=(386.41484, 217.69803), angle=90, dimstyle='Standard$0', override={"dimdec": 2, "dimpost": 'mm', "dimtmove": 2})
dim.commit()
dim.dimension.update_dxf_attribs({"geometry": '*D25', "text_midpoint": (389.04713, 223.17543), "dimtype": 160})
dim = msp.add_radius_dim(center=(384.00002, 218.42003), mpoint=(382.23225, 216.65226), dimstyle='Standard', override={"dimdec": 2, "dimpost": 'mm', "dimcen": 0})
dim.commit()
dim.dimension.update_dxf_attribs({"geometry": '*D26', "text_midpoint": (367.97493, 210.34495), "dimtype": 164})

# ---------------------------------------------------------------- leaders
for points in [[(382.00002, 196.30003), (382.00002, 179.30003)], [(395.00002, 196.30003), (395.00002, 187.80003)], [(421.00002, 196.77503), (421.00002, 179.77503)], [(447.00002, 197.25003), (447.00002, 188.75003)], [(489.00002, 197.50003), (489.00002, 189.00003)], [(302.37502, 195.80003), (302.37502, 178.80003)], [(372.00002, 196.00003), (372.00002, 187.50003)]]:
    msp.add_leader(points, dimstyle='Standard', override={"dimscale": 1, "dimasz": 2, "dimgap": 0.09, "dimtad": 0, "dimldrblk": 'ClosedBlank'})
msp.add_leader([(468.00002, 197.50003), (468.00002, 173.27401)], dimstyle='Standard', override={"dimscale": 1, "dimasz": 2, "dimgap": 0.09, "dimtad": 0, "dimldrblk": 'ClosedBlank'}, dxfattribs=at)

doc.saveas('drawing.dxf')
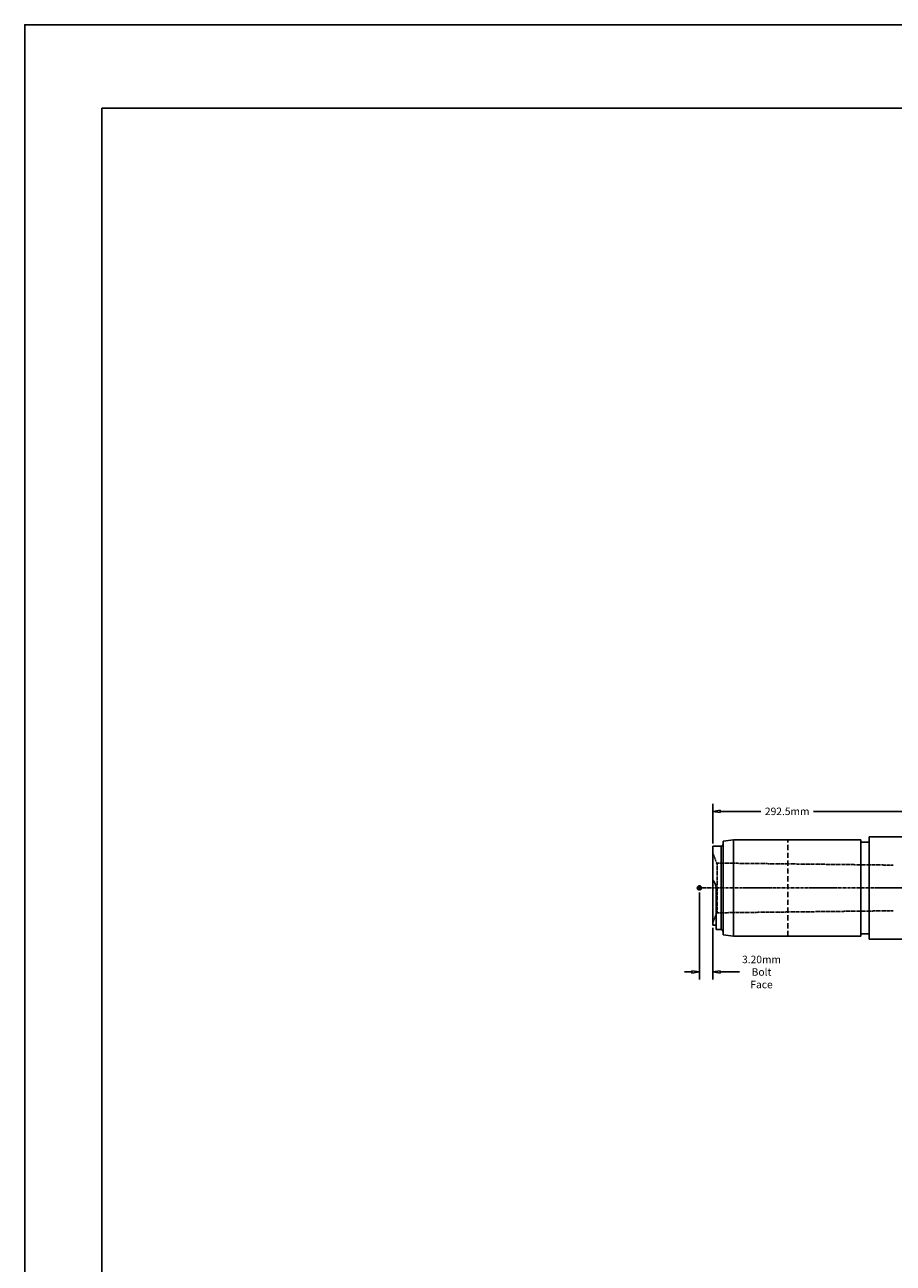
# Model space of a CAD drawing. Units: inches. Extents: x 0 to 841, y 0 to 594.
# Drawn here: x 0 to 208, y 297 to 594 of the extents above; entities that cross this region are included whole.
import ezdxf

# ---------------------------------------------------------------- set-up
doc = ezdxf.new("R2010")
doc.units = ezdxf.units.IN
doc.header["$MEASUREMENT"] = 0
doc.linetypes.add('CENTER2', pattern=[1.125, 0.75, -0.125, 0.125, -0.125])
doc.linetypes.add('HIDDEN2', pattern=[0.1875, 0.125, -0.0625])
for name, color, linetype in [('CENTER', 1, 'CENTER2'), ('CENTERLINE', 1, 'CENTER2'), ('HIDDEN', 5, 'HIDDEN2')]:
    doc.layers.add(name, color=color, linetype=linetype)
doc.dimstyles.new('Standard$0', dxfattribs={"dimscale": 10, "dimtxt": 0.18, "dimasz": 0.18, "dimexe": 0.18, "dimexo": 0.0625, "dimgap": 0.09, "dimtad": 0, "dimtih": 1, "dimtoh": 1, "dimdec": 4, "dimzin": 4, "dimdsep": 46, "dimtxsty": 'Standard', "dimblk": 'CLOSEDBLANK', "dimcen": 0.09, "dimadec": 5, "dimazin": 1, "dimtfac": 1, "dimtdec": 4, "dimtofl": 0, "dimtmove": 0, "dimatfit": 3, "dimldrblk": 'CLOSEDBLANK', "dimfxl": 0, "dimtolj": 1, "dimtzin": 0, "dimarcsym": 0})

# ---------------------------------------------------------------- blocks, each defined once
blk = doc.blocks.new('_ClosedBlank')
at = {"color": 0, "linetype": 'ByBlock', "lineweight": -2}
for p, q in [((-1, 0.17), (0, 0)), ((-1, 0.17), (-1, -0.17)), ((0, 0), (-1, -0.17))]:
    blk.add_line(p, q, dxfattribs=at)
blk = doc.blocks.new('*D27')
at = {"color": 0, "lineweight": -2}
for p, q in [((165, 397.63), (165, 407.17)), ((457.5, 389.88), (457.5, 407.17)), ((166.8, 405.37), (176.56, 405.37)), ((455.7, 405.37), (189.16, 405.37))]:
    blk.add_line(p, q, dxfattribs=at)
at = {"layer": 'Defpoints', "color": 0}
for p in [(457.5, 405.37), (165, 397), (457.5, 389.25)]:
    blk.add_point(p, dxfattribs=at)
at = {"color": 0, "lineweight": -2, "xscale": 1.8, "yscale": 1.8, "zscale": 1.8, "rotation": 180}
blk.add_blockref('_ClosedBlank', (165, 405.37), dxfattribs=at)
at = {"color": 0, "lineweight": -2, "xscale": 1.8, "yscale": 1.8, "zscale": 1.8}
blk.add_blockref('_ClosedBlank', (457.5, 405.37), dxfattribs=at)
at = {"color": 0, "insert": (182.86, 405.37), "char_height": 1.8, "attachment_point": 5}
blk.add_mtext('\\A1;292.5mm', dxfattribs=at)
blk = doc.blocks.new('*D30')
at = {"color": 0, "lineweight": -2}
for p, q in [((161.8, 385.88), (161.8, 365.05)), ((165, 377.44), (165, 365.05)), ((160, 366.85), (158.2, 366.85)), ((166.8, 366.85), (171.45, 366.85))]:
    blk.add_line(p, q, dxfattribs=at)
at = {"layer": 'Defpoints', "color": 0}
for p in [(161.8, 386.5), (165, 378.07), (165, 366.85)]:
    blk.add_point(p, dxfattribs=at)
at = {"color": 0, "lineweight": -2, "xscale": 1.8, "yscale": 1.8, "zscale": 1.8}
blk.add_blockref('_ClosedBlank', (161.8, 366.85), dxfattribs=at)
at = {"color": 0, "lineweight": -2, "xscale": 1.8, "yscale": 1.8, "zscale": 1.8, "rotation": 180}
blk.add_blockref('_ClosedBlank', (165, 366.85), dxfattribs=at)
at = {"color": 0, "insert": (176.7, 366.85), "char_height": 1.8, "attachment_point": 5}
blk.add_mtext('\\A1;3.20mm\\PBolt\\PFace', dxfattribs=at)

msp = doc.modelspace()

# ---------------------------------------------------------------- hatches: boundary and pattern name
at = {"layer": 'CENTER'}
h = msp.add_hatch(dxfattribs=at)
h.set_pattern_fill('ANSI31', color=256, style=0)
h.set_pattern_definition([(45, (112.80006, 337), (-0.08838835, 0.08838835), [])])
h.paths.add_polyline_path([(161.80002, 387.50003, 0.414213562), (161.30002, 387.00003), (161.80002, 387.00003)])
h.paths.add_polyline_path([(162.30002, 387.00003), (161.80002, 387.00003), (161.80002, 386.50003, 0.414213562)])

# ---------------------------------------------------------------- linework, layer by layer
for p, q in [((167.50002, 398.22807), (170.00002, 398.53503)), ((167.50002, 398.22807), (170.00002, 398.53503)), ((167.50002, 375.77199), (167.50002, 398.22807)), ((170.00002, 398.56503), (200.50002, 398.56503)), ((170.00002, 375.43503), (170.00002, 398.56503)), ((200.50002, 375.43503), (200.50002, 398.56503)), ((200.50002, 398.00003), (202.50002, 398.00003)), ((202.50002, 374.72503), (202.50002, 399.27503)), ((202.50002, 399.27503), (232.50002, 399.27503)), ((165.00002, 378.06974), (165.00002, 397.00003)), ((165.00002, 397.00003), (167.00002, 397.00003)), ((167.00002, 377.00003), (167.00002, 397.00003)), ((165.80002, 377.00003), (165.80002, 387.00003)), ((165.00002, 378.06974), (165.80002, 378.06974)), ((165.80002, 377.00003), (167.00002, 377.00003)), ((167.50002, 375.77199), (170.00002, 375.46503)), ((167.50002, 375.77199), (170.00002, 375.46503)), ((170.00002, 375.43503), (200.50002, 375.43503)), ((200.50002, 376.00003), (202.50002, 376.00003)), ((202.50002, 374.72503), (232.50002, 374.72503))]:
    msp.add_line(p, q)
at = {"linetype": 'HIDDEN2', "ltscale": 10}
msp.add_line((183.00002, 375.43503), (183.00002, 398.56503), dxfattribs=at)
for points in [[(-0.00009, 0.00003), (840.99991, 0.00003), (840.99991, 594.00003), (-0.00009, 594.00003)], [(18.49991, 20.00003), (822.49991, 20.00003), (822.49991, 574.00003), (18.49991, 574.00003)]]:
    msp.add_lwpolyline(points, close=True)
for centre, radius, start, end in [((167.00002, 397.50003), 0.5, 270, 0), ((163.30002, 387.00003), 2.5, 0, 47.156357), ((167.00002, 376.50003), 0.5, 0, 90)]:
    msp.add_arc(centre, radius, start, end)
at = {"layer": 'CENTER'}
msp.add_line((161.80002, 386.50003), (161.80002, 387.50003), dxfattribs=at)
msp.add_circle((161.80002, 387.00003), 0.5, dxfattribs=at)
at = {"layer": 'CENTERLINE'}
msp.add_line((161.30002, 387.00003), (718.00002, 387.00003), dxfattribs=at)
at = {"layer": 'HIDDEN'}
for p, q in [((166.02963, 392.6712), (165.00002, 395.50003)), ((165.92389, 392.9617), (208.2926, 392.47393)), ((166.02963, 381.32886), (166.02963, 392.6712)), ((166.02963, 381.32886), (165.00002, 378.50003)), ((165.92389, 381.03836), (208.2926, 381.52613))]:
    msp.add_line(p, q, dxfattribs=at)

# ---------------------------------------------------------------- dimensions: what is measured, and where the dimension line sits
dim = msp.add_linear_dim(base=(457.50002, 405.37243), p1=(165.00002, 397.00003), p2=(457.50002, 389.25003), dimstyle='Standard$0', override={"dimscale": 10, "dimdec": 1, "dimpost": 'mm', "dimblk1": 'ClosedBlank', "dimblk2": 'ClosedBlank', "dimsah": 1})
dim.commit()
dim.dimension.update_dxf_attribs({"geometry": '*D27', "text_midpoint": (182.85963, 405.37243), "dimtype": 160})
dim = msp.add_linear_dim(base=(165.00002, 366.84834), p1=(161.80002, 386.50003), p2=(165.00002, 378.06974), text='<>\\PBolt\\PFace', dimstyle='Standard$0', override={"dimdec": 2, "dimpost": 'mm'})
dim.commit()
dim.dimension.update_dxf_attribs({"geometry": '*D30', "text_midpoint": (176.70002, 366.84834), "dimtype": 160})

doc.saveas('drawing.dxf')
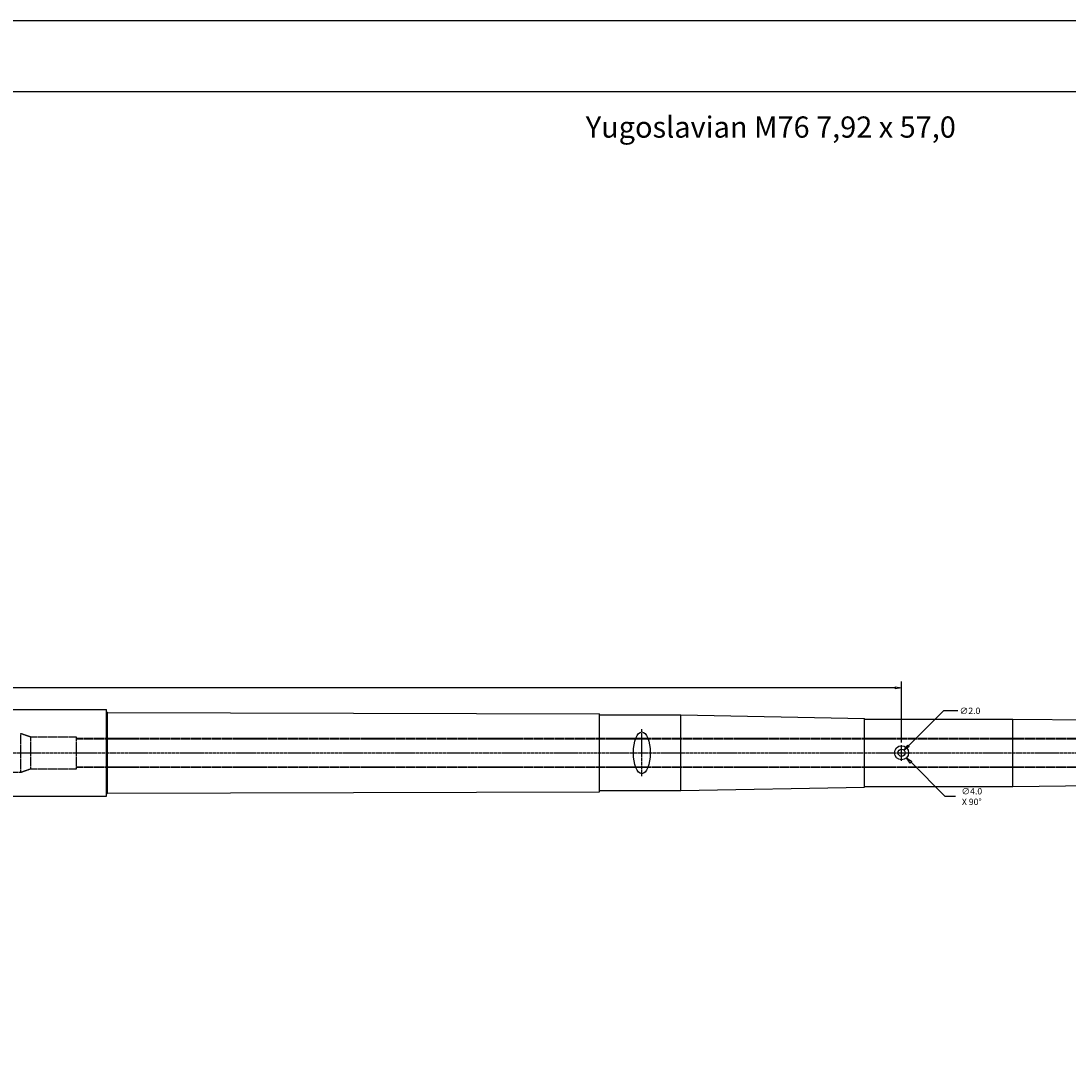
# Model space of a CAD drawing. Units: inches. Extents: x 0 to 841, y 0 to 594.
# Drawn here: x 208 to 505, y 297 to 594 of the extents above; entities that cross this region are included whole.
import ezdxf
from ezdxf.enums import TextEntityAlignment as Align

# ---------------------------------------------------------------- set-up
doc = ezdxf.new("R2010")
doc.units = ezdxf.units.IN
doc.header["$MEASUREMENT"] = 0
doc.linetypes.add('CENTER2', pattern=[1.125, 0.75, -0.125, 0.125, -0.125])
doc.linetypes.add('HIDDEN2', pattern=[0.1875, 0.125, -0.0625])
for name, color, linetype in [('CENTER', 1, 'CENTER2'), ('CENTERLINE', 1, 'CENTER2'), ('HIDDEN', 5, 'HIDDEN2')]:
    doc.layers.add(name, color=color, linetype=linetype)
doc.dimstyles.get("Standard").update_dxf_attribs({"dimscale": 10, "dimtxt": 0.18, "dimasz": 0.18, "dimexe": 0.18, "dimexo": 0.0625, "dimgap": 0.09, "dimtad": 0, "dimtih": 1, "dimtoh": 1, "dimdec": 4, "dimzin": 0, "dimdsep": 46, "dimtxsty": 'Standard', "dimblk": 'CLOSEDBLANK', "dimcen": 0.09, "dimadec": 4, "dimazin": 0, "dimtfac": 1, "dimtdec": 4, "dimtofl": 0, "dimtmove": 0, "dimatfit": 3, "dimldrblk": 'CLOSEDBLANK', "dimfxl": 0, "dimtolj": 1, "dimtzin": 0, "dimarcsym": 0})
doc.dimstyles.new('Standard$0', dxfattribs={"dimscale": 10, "dimtxt": 0.18, "dimasz": 0.18, "dimexe": 0.18, "dimexo": 0.0625, "dimgap": 0.09, "dimtad": 0, "dimtih": 1, "dimtoh": 1, "dimdec": 4, "dimzin": 4, "dimdsep": 46, "dimtxsty": 'Standard', "dimblk": 'CLOSEDBLANK', "dimcen": 0.09, "dimadec": 5, "dimazin": 1, "dimtfac": 1, "dimtdec": 4, "dimtofl": 0, "dimtmove": 0, "dimatfit": 3, "dimldrblk": 'CLOSEDBLANK', "dimfxl": 0, "dimtolj": 1, "dimtzin": 0, "dimarcsym": 0})

# ---------------------------------------------------------------- blocks, each defined once
blk = doc.blocks.new('_ClosedBlank')
at = {"color": 0, "linetype": 'ByBlock', "lineweight": -2}
for p, q in [((-1, 0.17), (0, 0)), ((-1, 0.17), (-1, -0.17)), ((0, 0), (-1, -0.17))]:
    blk.add_line(p, q, dxfattribs=at)
blk = doc.blocks.new('*D27')
at = {"color": 0, "lineweight": -2}
for p, q in [((165, 397.63), (165, 407.17)), ((457.5, 389.88), (457.5, 407.17)), ((166.8, 405.37), (176.56, 405.37)), ((455.7, 405.37), (189.16, 405.37))]:
    blk.add_line(p, q, dxfattribs=at)
at = {"layer": 'Defpoints', "color": 0}
for p in [(457.5, 405.37), (165, 397), (457.5, 389.25)]:
    blk.add_point(p, dxfattribs=at)
at = {"color": 0, "lineweight": -2, "xscale": 1.8, "yscale": 1.8, "zscale": 1.8, "rotation": 180}
blk.add_blockref('_ClosedBlank', (165, 405.37), dxfattribs=at)
at = {"color": 0, "lineweight": -2, "xscale": 1.8, "yscale": 1.8, "zscale": 1.8}
blk.add_blockref('_ClosedBlank', (457.5, 405.37), dxfattribs=at)
at = {"color": 0, "insert": (182.86, 405.37), "char_height": 1.8, "attachment_point": 5}
blk.add_mtext('\\A1;292.5mm', dxfattribs=at)
blk = doc.blocks.new('*D28')
at = {"color": 0, "lineweight": -2}
for p, q in [((469.37, 398.87), (459.48, 388.98)), ((473.42, 398.87), (469.37, 398.87)), ((456.6, 387), (458.4, 387)), ((457.5, 386.1), (457.5, 387.9))]:
    blk.add_line(p, q, dxfattribs=at)
at = {"layer": 'Defpoints', "color": 0}
for p in [(456.79, 386.29), (458.21, 387.71)]:
    blk.add_point(p, dxfattribs=at)
at = {"color": 0, "lineweight": -2, "xscale": 1.8, "yscale": 1.8, "zscale": 1.8, "rotation": 224.9999999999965}
blk.add_blockref('_ClosedBlank', (458.21, 387.71), dxfattribs=at)
at = {"color": 0, "insert": (476.87, 398.87), "char_height": 1.8, "attachment_point": 5}
blk.add_mtext('\\A1;∅2.0', dxfattribs=at)
blk = doc.blocks.new('*D29')
at = {"color": 0, "lineweight": -2}
for p, q in [((456.6, 387), (458.4, 387)), ((457.5, 386.1), (457.5, 387.9)), ((469.87, 374.63), (460.19, 384.31)), ((472.72, 374.63), (469.87, 374.63))]:
    blk.add_line(p, q, dxfattribs=at)
at = {"layer": 'Defpoints', "color": 0}
for p in [(456.09, 388.41), (458.91, 385.59)]:
    blk.add_point(p, dxfattribs=at)
at = {"color": 0, "lineweight": -2, "xscale": 1.8, "yscale": 1.8, "zscale": 1.8, "rotation": 135.0000000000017}
blk.add_blockref('_ClosedBlank', (458.91, 385.59), dxfattribs=at)
at = {"color": 0, "insert": (477.37, 374.63), "char_height": 1.8, "attachment_point": 5}
blk.add_mtext('\\A1;∅4.0\\PX 90%%d', dxfattribs=at)

msp = doc.modelspace()

# ---------------------------------------------------------------- linework, layer by layer
for p, q in [((202.50002, 399.27503), (232.50002, 399.27503)), ((232.50002, 374.72503), (232.50002, 399.27503)), ((232.75002, 375.60003), (232.75002, 398.40003)), ((232.75002, 398.40003), (372.00002, 398.00003)), ((372.00002, 376.00003), (372.00002, 398.00003)), ((372.00002, 397.70003), (395.00002, 397.70003)), ((395.00002, 397.70003), (447.00002, 396.75003)), ((395.00002, 376.30003), (395.00002, 397.70003)), ((447.00002, 377.25003), (447.00002, 396.75003)), ((447.00002, 396.50003), (489.00002, 396.50003)), ((489.00002, 396.50003), (674.50002, 394.75003)), ((489.00002, 377.50003), (489.00002, 396.50003)), ((395.00002, 376.30003), (447.00002, 377.25003)), ((447.00002, 377.50003), (489.00002, 377.50003)), ((489.00002, 377.50003), (674.50002, 379.25003)), ((202.50002, 374.72503), (232.50002, 374.72503)), ((232.75002, 375.60003), (372.00002, 376.00003)), ((372.00002, 376.30003), (395.00002, 376.30003))]:
    msp.add_line(p, q)
for points in [[(-0.00009, 0.00003), (840.99991, 0.00003), (840.99991, 594.00003), (-0.00009, 594.00003)], [(18.49991, 20.00003), (822.49991, 20.00003), (822.49991, 574.00003), (18.49991, 574.00003)]]:
    msp.add_lwpolyline(points, close=True)
for radius in [2, 1]:
    msp.add_circle((457.50002, 387.00003), radius)
for centre, start, end in [((232.75002, 398.65003), 180, 270), ((232.75002, 375.35003), 90, 180)]:
    msp.add_arc(centre, 0.25, start, end)
msp.add_ellipse((384.00002, 387.00003), major_axis=(0, -5.90962), ratio=0.405115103)
at = {"layer": 'CENTER'}
for p, q in [((384.00002, 380.35171), (384.00002, 393.64835)), ((457.50002, 384.75003), (457.50002, 389.25003))]:
    msp.add_line(p, q, dxfattribs=at)
at = {"layer": 'CENTERLINE'}
msp.add_line((161.30002, 387.00003), (718.00002, 387.00003), dxfattribs=at)
at = {"layer": 'HIDDEN'}
for p, q in [((208.2926, 392.47393), (211.11945, 391.49503)), ((208.2926, 381.52613), (208.2926, 392.47393)), ((208.3692, 392.44741), (211.11945, 391.49503)), ((211.11945, 391.49503), (224.01002, 391.49503)), ((211.11945, 382.50503), (211.11945, 391.49503)), ((224.01002, 382.50503), (224.01002, 391.49503)), ((224.01002, 391.10003), (715.00002, 391.10003)), ((224.01002, 390.94503), (715.00002, 390.94503)), ((165.92389, 381.03836), (208.2926, 381.52613)), ((208.2926, 381.52613), (211.03996, 382.4775)), ((208.3692, 381.55265), (211.11945, 382.50503)), ((211.11945, 382.50503), (224.01002, 382.50503)), ((224.01002, 383.05503), (715.00002, 383.05503)), ((224.01002, 382.90003), (715.00002, 382.90003))]:
    msp.add_line(p, q, dxfattribs=at)

# ---------------------------------------------------------------- texts
msp.add_text('Yugoslavian M76 7,92 x 57,0', height=6).set_placement((420.49991, 564.00003), align=Align.MIDDLE_CENTER)

# ---------------------------------------------------------------- dimensions: what is measured, and where the dimension line sits
dim = msp.add_linear_dim(base=(457.50002, 405.37243), p1=(165.00002, 397.00003), p2=(457.50002, 389.25003), dimstyle='Standard$0', override={"dimscale": 10, "dimdec": 1, "dimpost": 'mm', "dimblk1": 'ClosedBlank', "dimblk2": 'ClosedBlank', "dimsah": 1})
dim.commit()
dim.dimension.update_dxf_attribs({"geometry": '*D27', "text_midpoint": (182.85963, 405.37243), "dimtype": 160})
dim = msp.add_diameter_dim_2p(p1=(456.79291, 386.29292), p2=(458.20712, 387.70714), dimstyle='Standard', override={"dimdec": 1})
dim.commit()
dim.dimension.update_dxf_attribs({"geometry": '*D28', "text_midpoint": (476.86788, 398.8679), "dimtype": 163})
dim = msp.add_diameter_dim_2p(p1=(456.0858, 388.41424), p2=(458.91423, 385.58582), text='<>\\PX 90%%d', dimstyle='Standard', override={"dimdec": 1})
dim.commit()
dim.dimension.update_dxf_attribs({"geometry": '*D29', "text_midpoint": (477.36876, 374.63129), "dimtype": 163})

doc.saveas('drawing.dxf')
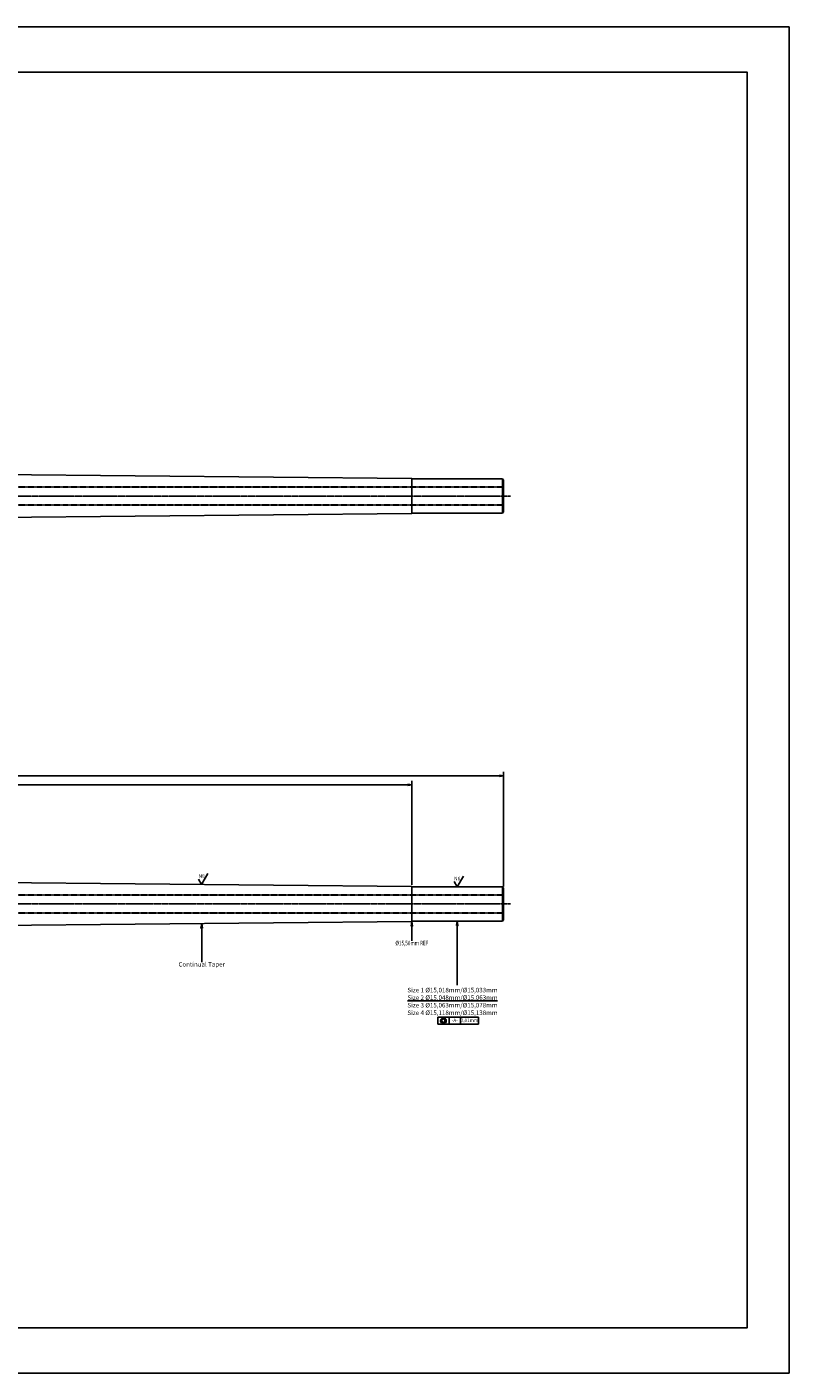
# Model space of a CAD drawing. Units: inches. Extents: x 0 to 841, y 0 to 594.
# Drawn here: x 505 to 841, y 0 to 594 of the extents above; entities that cross this region are included whole.
import ezdxf
from ezdxf.enums import TextEntityAlignment as Align

# ---------------------------------------------------------------- set-up
doc = ezdxf.new("R2010")
doc.units = ezdxf.units.IN
doc.header["$MEASUREMENT"] = 0
doc.linetypes.add('CENTER2', pattern=[1.125, 0.75, -0.125, 0.125, -0.125])
doc.linetypes.add('HIDDEN2', pattern=[0.1875, 0.125, -0.0625])
for name, color, linetype in [('CENTERLINE', 1, 'CENTER2'), ('HIDDEN', 5, 'HIDDEN2'), ('TEXT', 5, 'Continuous')]:
    doc.layers.add(name, color=color, linetype=linetype)
doc.dimstyles.get("Standard").update_dxf_attribs({"dimscale": 10, "dimtxt": 0.18, "dimasz": 0.18, "dimexe": 0.18, "dimexo": 0.0625, "dimgap": 0.09, "dimtad": 0, "dimtih": 1, "dimtoh": 1, "dimdec": 4, "dimzin": 0, "dimdsep": 46, "dimtxsty": 'Standard', "dimblk": 'CLOSEDBLANK', "dimcen": 0.09, "dimadec": 4, "dimazin": 0, "dimtfac": 1, "dimtdec": 4, "dimtofl": 0, "dimtmove": 0, "dimatfit": 3, "dimldrblk": 'CLOSEDBLANK', "dimfxl": 0, "dimtolj": 1, "dimtzin": 0, "dimarcsym": 0})
doc.dimstyles.new('Standard$0', dxfattribs={"dimscale": 10, "dimtxt": 0.18, "dimasz": 0.18, "dimexe": 0.18, "dimexo": 0.0625, "dimgap": 0.09, "dimtad": 0, "dimtih": 1, "dimtoh": 1, "dimdec": 4, "dimzin": 4, "dimdsep": 46, "dimtxsty": 'Standard', "dimblk": 'CLOSEDBLANK', "dimcen": 0.09, "dimadec": 5, "dimazin": 1, "dimtfac": 1, "dimtdec": 4, "dimtofl": 0, "dimtmove": 0, "dimatfit": 3, "dimldrblk": 'CLOSEDBLANK', "dimfxl": 0, "dimtolj": 1, "dimtzin": 0, "dimarcsym": 0})

# ---------------------------------------------------------------- blocks, each defined once
blk = doc.blocks.new('_ClosedBlank')
at = {"color": 0, "linetype": 'ByBlock', "lineweight": -2}
for p, q in [((-1, 0.17), (0, 0)), ((-1, 0.17), (-1, -0.17)), ((0, 0), (-1, -0.17))]:
    blk.add_line(p, q, dxfattribs=at)
blk = doc.blocks.new('*D14')
at = {"color": 0, "lineweight": -2}
for p, q in [((165, 217.63), (165, 261.35)), ((166.8, 259.55), (413.6, 259.55)), ((672.7, 259.55), (425.9, 259.55)), ((674.5, 215.38), (674.5, 261.35))]:
    blk.add_line(p, q, dxfattribs=at)
at = {"layer": 'Defpoints', "color": 0}
for p in [(674.5, 259.55), (165, 217), (674.5, 214.75)]:
    blk.add_point(p, dxfattribs=at)
at = {"color": 0, "lineweight": -2, "xscale": 1.8, "yscale": 1.8, "zscale": 1.8, "rotation": 180}
blk.add_blockref('_ClosedBlank', (165, 259.55), dxfattribs=at)
at = {"color": 0, "lineweight": -2, "xscale": 1.8, "yscale": 1.8, "zscale": 1.8}
blk.add_blockref('_ClosedBlank', (674.5, 259.55), dxfattribs=at)
at = {"color": 0, "insert": (419.75, 259.55), "char_height": 1.8, "attachment_point": 5}
blk.add_mtext('\\A1;509.5mm', dxfattribs=at)
blk = doc.blocks.new('*D15')
at = {"color": 0, "lineweight": -2}
for p, q in [((165, 217.63), (165, 265.35)), ((166.8, 263.55), (434, 263.55)), ((713.2, 263.55), (446, 263.55)), ((715, 214.65), (715, 265.35))]:
    blk.add_line(p, q, dxfattribs=at)
at = {"layer": 'Defpoints', "color": 0}
for p in [(715, 263.55), (165, 217), (715, 214.03)]:
    blk.add_point(p, dxfattribs=at)
at = {"color": 0, "lineweight": -2, "xscale": 1.8, "yscale": 1.8, "zscale": 1.8, "rotation": 180}
blk.add_blockref('_ClosedBlank', (165, 263.55), dxfattribs=at)
at = {"color": 0, "lineweight": -2, "xscale": 1.8, "yscale": 1.8, "zscale": 1.8}
blk.add_blockref('_ClosedBlank', (715, 263.55), dxfattribs=at)
at = {"color": 0, "insert": (440, 263.55), "char_height": 1.8, "attachment_point": 5}
blk.add_mtext('\\A1;550.0mm', dxfattribs=at)

msp = doc.modelspace()

# ---------------------------------------------------------------- linework, layer by layer
for p, q in [((489.00002, 396.50003), (674.50002, 394.75003)), ((674.50002, 379.25003), (674.50002, 394.75003)), ((674.50002, 394.52503), (714.50002, 394.52503)), ((714.50002, 379.47503), (714.50002, 394.52503)), ((714.50002, 394.52503), (715.00002, 394.02503)), ((715.00002, 379.97503), (715.00002, 394.02503)), ((489.00002, 377.50003), (674.50002, 379.25003)), ((674.50002, 379.47503), (714.50002, 379.47503)), ((714.50002, 379.47503), (715.00002, 379.97503)), ((581.72879, 215.62523), (584.47842, 220.38773)), ((489.00002, 216.50003), (674.50002, 214.75003)), ((580.35398, 218.00648), (581.72879, 215.62523)), ((674.50002, 199.25003), (674.50002, 214.75003)), ((674.50002, 214.52503), (714.50002, 214.52503)), ((693.1252, 216.90628), (694.50002, 214.52503)), ((694.50002, 214.52503), (697.24965, 219.28753)), ((714.50002, 199.47503), (714.50002, 214.52503)), ((714.50002, 214.52503), (715.00002, 214.02503)), ((715.00002, 199.97503), (715.00002, 214.02503)), ((489.00002, 197.50003), (674.50002, 199.25003)), ((674.50002, 199.47503), (714.50002, 199.47503)), ((714.50002, 199.47503), (715.00002, 199.97503))]:
    msp.add_line(p, q)
for points in [[(-0.00009, 0.00003), (840.99991, 0.00003), (840.99991, 594.00003), (-0.00009, 594.00003)], [(18.49991, 20.00003), (822.49991, 20.00003), (822.49991, 574.00003), (18.49991, 574.00003)]]:
    msp.add_lwpolyline(points, close=True)
at = {"layer": 'CENTERLINE'}
for p, q in [((161.30002, 387.00003), (718.00002, 387.00003)), ((161.30002, 207.00003), (718.00002, 207.00003))]:
    msp.add_line(p, q, dxfattribs=at)
at = {"layer": 'HIDDEN'}
for p, q in [((224.01002, 391.10003), (715.00002, 391.10003)), ((224.01002, 390.94503), (715.00002, 390.94503)), ((224.01002, 383.05503), (715.00002, 383.05503)), ((224.01002, 382.90003), (715.00002, 382.90003)), ((224.01002, 211.10003), (715.00002, 211.10003)), ((224.01002, 210.94503), (715.00002, 210.94503)), ((224.01002, 203.05503), (715.00002, 203.05503)), ((224.01002, 202.90003), (715.00002, 202.90003))]:
    msp.add_line(p, q, dxfattribs=at)
at = {"layer": 'TEXT', "color": 7}
for p, q in [((685.93463, 154), (685.93463, 157)), ((685.93463, 157), (690.93463, 157)), ((690.93463, 157), (695.93463, 157)), ((690.93463, 154), (690.93463, 157)), ((695.93463, 157), (703.93463, 157)), ((695.93463, 154), (695.93463, 157)), ((703.93463, 154), (703.93463, 157)), ((685.93463, 154), (690.93463, 154)), ((690.93463, 154), (695.93463, 154)), ((695.93463, 154), (703.93463, 154))]:
    msp.add_line(p, q, dxfattribs=at)
for radius in [1.25, 0.75]:
    msp.add_circle((688.43463, 155.5), radius, dxfattribs=at)

# ---------------------------------------------------------------- texts
for s, p in [('N8', (581.72879, 218.00648)), ('N6', (694.50002, 216.90628))]:
    msp.add_text(s, height=1.5875).set_placement(p, align=Align.BOTTOM_CENTER)
at = {"char_height": 2, "width": 28.6395508, "attachment_point": 2}
for s, insert in [('\\A1;{\\W0.75;%%C15,50mm REF}', (674.50002, 190.75003)), ('\\A1;Continual Taper', (581.75002, 181.37503))]:
    msp.add_mtext(s, dxfattribs=dict(at, insert=insert))
at = {"layer": 'TEXT', "color": 7}
for s, insert, char_height, width, attachment_point in [('\\A1;Size 1 %%C15,018mm/%%C15,033mm\\P{\\LSize 2 %%C15,048mm/%%C15,063mm}\\PSize 3 %%C15,063mm/%%C15,078mm\\PSize 4 %%C15,118mm/%%C15,138mm', (672.5432, 170), 2, 48.5376086, 1), ('-A-', (693.43463, 155.5), 1.5, 1.19634, 5), ('0,01mm', (699.93463, 155.5), 1.5, 6.6720954, 5)]:
    msp.add_mtext(s, dxfattribs=dict(at, insert=insert, char_height=char_height, width=width, attachment_point=attachment_point))

# ---------------------------------------------------------------- dimensions: what is measured, and where the dimension line sits
for base, p2, picture, middle in [((715.00002, 263.5467), (715.00002, 214.02503), '*D15', (440.00002, 263.5467)), ((674.50002, 259.5467), (674.50002, 214.75003), '*D14', (419.75002, 259.5467))]:
    dim = msp.add_linear_dim(base=base, p1=(165.00002, 217.00003), p2=p2, dimstyle='Standard$0', override={"dimscale": 10, "dimdec": 1, "dimpost": 'mm', "dimblk1": 'ClosedBlank', "dimblk2": 'ClosedBlank', "dimsah": 1})
    dim.commit()
    dim.dimension.update_dxf_attribs({"geometry": picture, "text_midpoint": middle})

# ---------------------------------------------------------------- leaders
for points in [[(581.75002, 198.37503), (581.75002, 181.37503)], [(674.50002, 199.25003), (674.50002, 190.75003)]]:
    msp.add_leader(points, dimstyle='Standard', override={"dimscale": 1, "dimasz": 2, "dimgap": 0.09, "dimtad": 0, "dimldrblk": 'ClosedBlank'})
msp.add_leader([(694.50002, 199.47503), (694.50002, 171.23901)], dimstyle='Standard', override={"dimscale": 1, "dimasz": 2, "dimgap": 0.09, "dimtad": 0, "dimldrblk": 'ClosedBlank'}, dxfattribs=at)

doc.saveas('drawing.dxf')
